# Generated by FakeRAM 2.0
VERSION 5.7 ;
BUSBITCHARS "[]" ;
PROPERTYDEFINITIONS
  MACRO width INTEGER ;
  MACRO depth INTEGER ;
  MACRO banks INTEGER ;
END PROPERTYDEFINITIONS
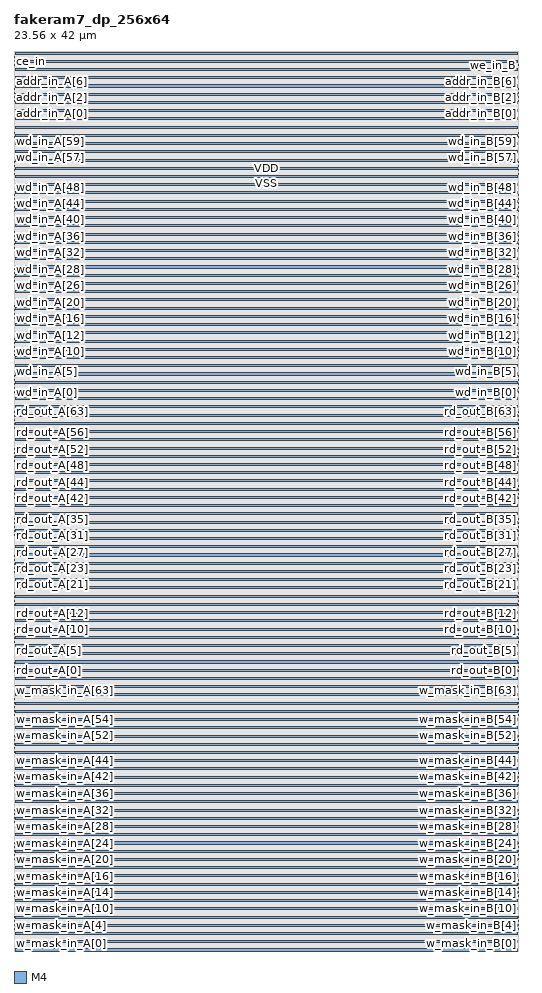
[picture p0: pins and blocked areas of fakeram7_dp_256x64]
MACRO fakeram7_dp_256x64
  PROPERTY width 64 ;
  PROPERTY depth 256 ;
  PROPERTY banks 2 ;
  FOREIGN fakeram7_dp_256x64 0 0 ;
  SYMMETRY X Y ;
  SIZE 23.560 BY 42.000 ;
  CLASS BLOCK ;
  PIN w_mask_in_A[0]
    DIRECTION INPUT ;
    USE SIGNAL ;
    SHAPE ABUTMENT ;
    PORT
      LAYER M4 ;
      RECT 0.000 0.048 0.024 0.072 ;
    END
  END w_mask_in_A[0]
  PIN w_mask_in_B[0]
    DIRECTION INPUT ;
    USE SIGNAL ;
    SHAPE ABUTMENT ;
    PORT
      LAYER M4 ;
      RECT 23.536 0.048 23.560 0.072 ;
    END
  END w_mask_in_B[0]
  PIN w_mask_in_A[1]
    DIRECTION INPUT ;
    USE SIGNAL ;
    SHAPE ABUTMENT ;
    PORT
      LAYER M4 ;
      RECT 0.000 0.240 0.024 0.264 ;
    END
  END w_mask_in_A[1]
  PIN w_mask_in_B[1]
    DIRECTION INPUT ;
    USE SIGNAL ;
    SHAPE ABUTMENT ;
    PORT
      LAYER M4 ;
      RECT 23.536 0.240 23.560 0.264 ;
    END
  END w_mask_in_B[1]
  PIN w_mask_in_A[2]
    DIRECTION INPUT ;
    USE SIGNAL ;
    SHAPE ABUTMENT ;
    PORT
      LAYER M4 ;
      RECT 0.000 0.432 0.024 0.456 ;
    END
  END w_mask_in_A[2]
  PIN w_mask_in_B[2]
    DIRECTION INPUT ;
    USE SIGNAL ;
    SHAPE ABUTMENT ;
    PORT
      LAYER M4 ;
      RECT 23.536 0.432 23.560 0.456 ;
    END
  END w_mask_in_B[2]
  PIN w_mask_in_A[3]
    DIRECTION INPUT ;
    USE SIGNAL ;
    SHAPE ABUTMENT ;
    PORT
      LAYER M4 ;
      RECT 0.000 0.624 0.024 0.648 ;
    END
  END w_mask_in_A[3]
  PIN w_mask_in_B[3]
    DIRECTION INPUT ;
    USE SIGNAL ;
    SHAPE ABUTMENT ;
    PORT
      LAYER M4 ;
      RECT 23.536 0.624 23.560 0.648 ;
    END
  END w_mask_in_B[3]
  PIN w_mask_in_A[4]
    DIRECTION INPUT ;
    USE SIGNAL ;
    SHAPE ABUTMENT ;
    PORT
      LAYER M4 ;
      RECT 0.000 0.816 0.024 0.840 ;
    END
  END w_mask_in_A[4]
  PIN w_mask_in_B[4]
    DIRECTION INPUT ;
    USE SIGNAL ;
    SHAPE ABUTMENT ;
    PORT
      LAYER M4 ;
      RECT 23.536 0.816 23.560 0.840 ;
    END
  END w_mask_in_B[4]
  PIN w_mask_in_A[5]
    DIRECTION INPUT ;
    USE SIGNAL ;
    SHAPE ABUTMENT ;
    PORT
      LAYER M4 ;
      RECT 0.000 1.008 0.024 1.032 ;
    END
  END w_mask_in_A[5]
  PIN w_mask_in_B[5]
    DIRECTION INPUT ;
    USE SIGNAL ;
    SHAPE ABUTMENT ;
    PORT
      LAYER M4 ;
      RECT 23.536 1.008 23.560 1.032 ;
    END
  END w_mask_in_B[5]
  PIN w_mask_in_A[6]
    DIRECTION INPUT ;
    USE SIGNAL ;
    SHAPE ABUTMENT ;
    PORT
      LAYER M4 ;
      RECT 0.000 1.200 0.024 1.224 ;
    END
  END w_mask_in_A[6]
  PIN w_mask_in_B[6]
    DIRECTION INPUT ;
    USE SIGNAL ;
    SHAPE ABUTMENT ;
    PORT
      LAYER M4 ;
      RECT 23.536 1.200 23.560 1.224 ;
    END
  END w_mask_in_B[6]
  PIN w_mask_in_A[7]
    DIRECTION INPUT ;
    USE SIGNAL ;
    SHAPE ABUTMENT ;
    PORT
      LAYER M4 ;
      RECT 0.000 1.392 0.024 1.416 ;
    END
  END w_mask_in_A[7]
  PIN w_mask_in_B[7]
    DIRECTION INPUT ;
    USE SIGNAL ;
    SHAPE ABUTMENT ;
    PORT
      LAYER M4 ;
      RECT 23.536 1.392 23.560 1.416 ;
    END
  END w_mask_in_B[7]
  PIN w_mask_in_A[8]
    DIRECTION INPUT ;
    USE SIGNAL ;
    SHAPE ABUTMENT ;
    PORT
      LAYER M4 ;
      RECT 0.000 1.584 0.024 1.608 ;
    END
  END w_mask_in_A[8]
  PIN w_mask_in_B[8]
    DIRECTION INPUT ;
    USE SIGNAL ;
    SHAPE ABUTMENT ;
    PORT
      LAYER M4 ;
      RECT 23.536 1.584 23.560 1.608 ;
    END
  END w_mask_in_B[8]
  PIN w_mask_in_A[9]
    DIRECTION INPUT ;
    USE SIGNAL ;
    SHAPE ABUTMENT ;
    PORT
      LAYER M4 ;
      RECT 0.000 1.776 0.024 1.800 ;
    END
  END w_mask_in_A[9]
  PIN w_mask_in_B[9]
    DIRECTION INPUT ;
    USE SIGNAL ;
    SHAPE ABUTMENT ;
    PORT
      LAYER M4 ;
      RECT 23.536 1.776 23.560 1.800 ;
    END
  END w_mask_in_B[9]
  PIN w_mask_in_A[10]
    DIRECTION INPUT ;
    USE SIGNAL ;
    SHAPE ABUTMENT ;
    PORT
      LAYER M4 ;
      RECT 0.000 1.968 0.024 1.992 ;
    END
  END w_mask_in_A[10]
  PIN w_mask_in_B[10]
    DIRECTION INPUT ;
    USE SIGNAL ;
    SHAPE ABUTMENT ;
    PORT
      LAYER M4 ;
      RECT 23.536 1.968 23.560 1.992 ;
    END
  END w_mask_in_B[10]
  PIN w_mask_in_A[11]
    DIRECTION INPUT ;
    USE SIGNAL ;
    SHAPE ABUTMENT ;
    PORT
      LAYER M4 ;
      RECT 0.000 2.160 0.024 2.184 ;
    END
  END w_mask_in_A[11]
  PIN w_mask_in_B[11]
    DIRECTION INPUT ;
    USE SIGNAL ;
    SHAPE ABUTMENT ;
    PORT
      LAYER M4 ;
      RECT 23.536 2.160 23.560 2.184 ;
    END
  END w_mask_in_B[11]
  PIN w_mask_in_A[12]
    DIRECTION INPUT ;
    USE SIGNAL ;
    SHAPE ABUTMENT ;
    PORT
      LAYER M4 ;
      RECT 0.000 2.352 0.024 2.376 ;
    END
  END w_mask_in_A[12]
  PIN w_mask_in_B[12]
    DIRECTION INPUT ;
    USE SIGNAL ;
    SHAPE ABUTMENT ;
    PORT
      LAYER M4 ;
      RECT 23.536 2.352 23.560 2.376 ;
    END
  END w_mask_in_B[12]
  PIN w_mask_in_A[13]
    DIRECTION INPUT ;
    USE SIGNAL ;
    SHAPE ABUTMENT ;
    PORT
      LAYER M4 ;
      RECT 0.000 2.544 0.024 2.568 ;
    END
  END w_mask_in_A[13]
  PIN w_mask_in_B[13]
    DIRECTION INPUT ;
    USE SIGNAL ;
    SHAPE ABUTMENT ;
    PORT
      LAYER M4 ;
      RECT 23.536 2.544 23.560 2.568 ;
    END
  END w_mask_in_B[13]
  PIN w_mask_in_A[14]
    DIRECTION INPUT ;
    USE SIGNAL ;
    SHAPE ABUTMENT ;
    PORT
      LAYER M4 ;
      RECT 0.000 2.736 0.024 2.760 ;
    END
  END w_mask_in_A[14]
  PIN w_mask_in_B[14]
    DIRECTION INPUT ;
    USE SIGNAL ;
    SHAPE ABUTMENT ;
    PORT
      LAYER M4 ;
      RECT 23.536 2.736 23.560 2.760 ;
    END
  END w_mask_in_B[14]
  PIN w_mask_in_A[15]
    DIRECTION INPUT ;
    USE SIGNAL ;
    SHAPE ABUTMENT ;
    PORT
      LAYER M4 ;
      RECT 0.000 2.928 0.024 2.952 ;
    END
  END w_mask_in_A[15]
  PIN w_mask_in_B[15]
    DIRECTION INPUT ;
    USE SIGNAL ;
    SHAPE ABUTMENT ;
    PORT
      LAYER M4 ;
      RECT 23.536 2.928 23.560 2.952 ;
    END
  END w_mask_in_B[15]
  PIN w_mask_in_A[16]
    DIRECTION INPUT ;
    USE SIGNAL ;
    SHAPE ABUTMENT ;
    PORT
      LAYER M4 ;
      RECT 0.000 3.120 0.024 3.144 ;
    END
  END w_mask_in_A[16]
  PIN w_mask_in_B[16]
    DIRECTION INPUT ;
    USE SIGNAL ;
    SHAPE ABUTMENT ;
    PORT
      LAYER M4 ;
      RECT 23.536 3.120 23.560 3.144 ;
    END
  END w_mask_in_B[16]
  PIN w_mask_in_A[17]
    DIRECTION INPUT ;
    USE SIGNAL ;
    SHAPE ABUTMENT ;
    PORT
      LAYER M4 ;
      RECT 0.000 3.312 0.024 3.336 ;
    END
  END w_mask_in_A[17]
  PIN w_mask_in_B[17]
    DIRECTION INPUT ;
    USE SIGNAL ;
    SHAPE ABUTMENT ;
    PORT
      LAYER M4 ;
      RECT 23.536 3.312 23.560 3.336 ;
    END
  END w_mask_in_B[17]
  PIN w_mask_in_A[18]
    DIRECTION INPUT ;
    USE SIGNAL ;
    SHAPE ABUTMENT ;
    PORT
      LAYER M4 ;
      RECT 0.000 3.504 0.024 3.528 ;
    END
  END w_mask_in_A[18]
  PIN w_mask_in_B[18]
    DIRECTION INPUT ;
    USE SIGNAL ;
    SHAPE ABUTMENT ;
    PORT
      LAYER M4 ;
      RECT 23.536 3.504 23.560 3.528 ;
    END
  END w_mask_in_B[18]
  PIN w_mask_in_A[19]
    DIRECTION INPUT ;
    USE SIGNAL ;
    SHAPE ABUTMENT ;
    PORT
      LAYER M4 ;
      RECT 0.000 3.696 0.024 3.720 ;
    END
  END w_mask_in_A[19]
  PIN w_mask_in_B[19]
    DIRECTION INPUT ;
    USE SIGNAL ;
    SHAPE ABUTMENT ;
    PORT
      LAYER M4 ;
      RECT 23.536 3.696 23.560 3.720 ;
    END
  END w_mask_in_B[19]
  PIN w_mask_in_A[20]
    DIRECTION INPUT ;
    USE SIGNAL ;
    SHAPE ABUTMENT ;
    PORT
      LAYER M4 ;
      RECT 0.000 3.888 0.024 3.912 ;
    END
  END w_mask_in_A[20]
  PIN w_mask_in_B[20]
    DIRECTION INPUT ;
    USE SIGNAL ;
    SHAPE ABUTMENT ;
    PORT
      LAYER M4 ;
      RECT 23.536 3.888 23.560 3.912 ;
    END
  END w_mask_in_B[20]
  PIN w_mask_in_A[21]
    DIRECTION INPUT ;
    USE SIGNAL ;
    SHAPE ABUTMENT ;
    PORT
      LAYER M4 ;
      RECT 0.000 4.080 0.024 4.104 ;
    END
  END w_mask_in_A[21]
  PIN w_mask_in_B[21]
    DIRECTION INPUT ;
    USE SIGNAL ;
    SHAPE ABUTMENT ;
    PORT
      LAYER M4 ;
      RECT 23.536 4.080 23.560 4.104 ;
    END
  END w_mask_in_B[21]
  PIN w_mask_in_A[22]
    DIRECTION INPUT ;
    USE SIGNAL ;
    SHAPE ABUTMENT ;
    PORT
      LAYER M4 ;
      RECT 0.000 4.272 0.024 4.296 ;
    END
  END w_mask_in_A[22]
  PIN w_mask_in_B[22]
    DIRECTION INPUT ;
    USE SIGNAL ;
    SHAPE ABUTMENT ;
    PORT
      LAYER M4 ;
      RECT 23.536 4.272 23.560 4.296 ;
    END
  END w_mask_in_B[22]
  PIN w_mask_in_A[23]
    DIRECTION INPUT ;
    USE SIGNAL ;
    SHAPE ABUTMENT ;
    PORT
      LAYER M4 ;
      RECT 0.000 4.464 0.024 4.488 ;
    END
  END w_mask_in_A[23]
  PIN w_mask_in_B[23]
    DIRECTION INPUT ;
    USE SIGNAL ;
    SHAPE ABUTMENT ;
    PORT
      LAYER M4 ;
      RECT 23.536 4.464 23.560 4.488 ;
    END
  END w_mask_in_B[23]
  PIN w_mask_in_A[24]
    DIRECTION INPUT ;
    USE SIGNAL ;
    SHAPE ABUTMENT ;
    PORT
      LAYER M4 ;
      RECT 0.000 4.656 0.024 4.680 ;
    END
  END w_mask_in_A[24]
  PIN w_mask_in_B[24]
    DIRECTION INPUT ;
    USE SIGNAL ;
    SHAPE ABUTMENT ;
    PORT
      LAYER M4 ;
      RECT 23.536 4.656 23.560 4.680 ;
    END
  END w_mask_in_B[24]
  PIN w_mask_in_A[25]
    DIRECTION INPUT ;
    USE SIGNAL ;
    SHAPE ABUTMENT ;
    PORT
      LAYER M4 ;
      RECT 0.000 4.848 0.024 4.872 ;
    END
  END w_mask_in_A[25]
  PIN w_mask_in_B[25]
    DIRECTION INPUT ;
    USE SIGNAL ;
    SHAPE ABUTMENT ;
    PORT
      LAYER M4 ;
      RECT 23.536 4.848 23.560 4.872 ;
    END
  END w_mask_in_B[25]
  PIN w_mask_in_A[26]
    DIRECTION INPUT ;
    USE SIGNAL ;
    SHAPE ABUTMENT ;
    PORT
      LAYER M4 ;
      RECT 0.000 5.040 0.024 5.064 ;
    END
  END w_mask_in_A[26]
  PIN w_mask_in_B[26]
    DIRECTION INPUT ;
    USE SIGNAL ;
    SHAPE ABUTMENT ;
    PORT
      LAYER M4 ;
      RECT 23.536 5.040 23.560 5.064 ;
    END
  END w_mask_in_B[26]
  PIN w_mask_in_A[27]
    DIRECTION INPUT ;
    USE SIGNAL ;
    SHAPE ABUTMENT ;
    PORT
      LAYER M4 ;
      RECT 0.000 5.232 0.024 5.256 ;
    END
  END w_mask_in_A[27]
  PIN w_mask_in_B[27]
    DIRECTION INPUT ;
    USE SIGNAL ;
    SHAPE ABUTMENT ;
    PORT
      LAYER M4 ;
      RECT 23.536 5.232 23.560 5.256 ;
    END
  END w_mask_in_B[27]
  PIN w_mask_in_A[28]
    DIRECTION INPUT ;
    USE SIGNAL ;
    SHAPE ABUTMENT ;
    PORT
      LAYER M4 ;
      RECT 0.000 5.424 0.024 5.448 ;
    END
  END w_mask_in_A[28]
  PIN w_mask_in_B[28]
    DIRECTION INPUT ;
    USE SIGNAL ;
    SHAPE ABUTMENT ;
    PORT
      LAYER M4 ;
      RECT 23.536 5.424 23.560 5.448 ;
    END
  END w_mask_in_B[28]
  PIN w_mask_in_A[29]
    DIRECTION INPUT ;
    USE SIGNAL ;
    SHAPE ABUTMENT ;
    PORT
      LAYER M4 ;
      RECT 0.000 5.616 0.024 5.640 ;
    END
  END w_mask_in_A[29]
  PIN w_mask_in_B[29]
    DIRECTION INPUT ;
    USE SIGNAL ;
    SHAPE ABUTMENT ;
    PORT
      LAYER M4 ;
      RECT 23.536 5.616 23.560 5.640 ;
    END
  END w_mask_in_B[29]
  PIN w_mask_in_A[30]
    DIRECTION INPUT ;
    USE SIGNAL ;
    SHAPE ABUTMENT ;
    PORT
      LAYER M4 ;
      RECT 0.000 5.808 0.024 5.832 ;
    END
  END w_mask_in_A[30]
  PIN w_mask_in_B[30]
    DIRECTION INPUT ;
    USE SIGNAL ;
    SHAPE ABUTMENT ;
    PORT
      LAYER M4 ;
      RECT 23.536 5.808 23.560 5.832 ;
    END
  END w_mask_in_B[30]
  PIN w_mask_in_A[31]
    DIRECTION INPUT ;
    USE SIGNAL ;
    SHAPE ABUTMENT ;
    PORT
      LAYER M4 ;
      RECT 0.000 6.000 0.024 6.024 ;
    END
  END w_mask_in_A[31]
  PIN w_mask_in_B[31]
    DIRECTION INPUT ;
    USE SIGNAL ;
    SHAPE ABUTMENT ;
    PORT
      LAYER M4 ;
      RECT 23.536 6.000 23.560 6.024 ;
    END
  END w_mask_in_B[31]
  PIN w_mask_in_A[32]
    DIRECTION INPUT ;
    USE SIGNAL ;
    SHAPE ABUTMENT ;
    PORT
      LAYER M4 ;
      RECT 0.000 6.192 0.024 6.216 ;
    END
  END w_mask_in_A[32]
  PIN w_mask_in_B[32]
    DIRECTION INPUT ;
    USE SIGNAL ;
    SHAPE ABUTMENT ;
    PORT
      LAYER M4 ;
      RECT 23.536 6.192 23.560 6.216 ;
    END
  END w_mask_in_B[32]
  PIN w_mask_in_A[33]
    DIRECTION INPUT ;
    USE SIGNAL ;
    SHAPE ABUTMENT ;
    PORT
      LAYER M4 ;
      RECT 0.000 6.384 0.024 6.408 ;
    END
  END w_mask_in_A[33]
  PIN w_mask_in_B[33]
    DIRECTION INPUT ;
    USE SIGNAL ;
    SHAPE ABUTMENT ;
    PORT
      LAYER M4 ;
      RECT 23.536 6.384 23.560 6.408 ;
    END
  END w_mask_in_B[33]
  PIN w_mask_in_A[34]
    DIRECTION INPUT ;
    USE SIGNAL ;
    SHAPE ABUTMENT ;
    PORT
      LAYER M4 ;
      RECT 0.000 6.576 0.024 6.600 ;
    END
  END w_mask_in_A[34]
  PIN w_mask_in_B[34]
    DIRECTION INPUT ;
    USE SIGNAL ;
    SHAPE ABUTMENT ;
    PORT
      LAYER M4 ;
      RECT 23.536 6.576 23.560 6.600 ;
    END
  END w_mask_in_B[34]
  PIN w_mask_in_A[35]
    DIRECTION INPUT ;
    USE SIGNAL ;
    SHAPE ABUTMENT ;
    PORT
      LAYER M4 ;
      RECT 0.000 6.768 0.024 6.792 ;
    END
  END w_mask_in_A[35]
  PIN w_mask_in_B[35]
    DIRECTION INPUT ;
    USE SIGNAL ;
    SHAPE ABUTMENT ;
    PORT
      LAYER M4 ;
      RECT 23.536 6.768 23.560 6.792 ;
    END
  END w_mask_in_B[35]
  PIN w_mask_in_A[36]
    DIRECTION INPUT ;
    USE SIGNAL ;
    SHAPE ABUTMENT ;
    PORT
      LAYER M4 ;
      RECT 0.000 6.960 0.024 6.984 ;
    END
  END w_mask_in_A[36]
  PIN w_mask_in_B[36]
    DIRECTION INPUT ;
    USE SIGNAL ;
    SHAPE ABUTMENT ;
    PORT
      LAYER M4 ;
      RECT 23.536 6.960 23.560 6.984 ;
    END
  END w_mask_in_B[36]
  PIN w_mask_in_A[37]
    DIRECTION INPUT ;
    USE SIGNAL ;
    SHAPE ABUTMENT ;
    PORT
      LAYER M4 ;
      RECT 0.000 7.152 0.024 7.176 ;
    END
  END w_mask_in_A[37]
  PIN w_mask_in_B[37]
    DIRECTION INPUT ;
    USE SIGNAL ;
    SHAPE ABUTMENT ;
    PORT
      LAYER M4 ;
      RECT 23.536 7.152 23.560 7.176 ;
    END
  END w_mask_in_B[37]
  PIN w_mask_in_A[38]
    DIRECTION INPUT ;
    USE SIGNAL ;
    SHAPE ABUTMENT ;
    PORT
      LAYER M4 ;
      RECT 0.000 7.344 0.024 7.368 ;
    END
  END w_mask_in_A[38]
  PIN w_mask_in_B[38]
    DIRECTION INPUT ;
    USE SIGNAL ;
    SHAPE ABUTMENT ;
    PORT
      LAYER M4 ;
      RECT 23.536 7.344 23.560 7.368 ;
    END
  END w_mask_in_B[38]
  PIN w_mask_in_A[39]
    DIRECTION INPUT ;
    USE SIGNAL ;
    SHAPE ABUTMENT ;
    PORT
      LAYER M4 ;
      RECT 0.000 7.536 0.024 7.560 ;
    END
  END w_mask_in_A[39]
  PIN w_mask_in_B[39]
    DIRECTION INPUT ;
    USE SIGNAL ;
    SHAPE ABUTMENT ;
    PORT
      LAYER M4 ;
      RECT 23.536 7.536 23.560 7.560 ;
    END
  END w_mask_in_B[39]
  PIN w_mask_in_A[40]
    DIRECTION INPUT ;
    USE SIGNAL ;
    SHAPE ABUTMENT ;
    PORT
      LAYER M4 ;
      RECT 0.000 7.728 0.024 7.752 ;
    END
  END w_mask_in_A[40]
  PIN w_mask_in_B[40]
    DIRECTION INPUT ;
    USE SIGNAL ;
    SHAPE ABUTMENT ;
    PORT
      LAYER M4 ;
      RECT 23.536 7.728 23.560 7.752 ;
    END
  END w_mask_in_B[40]
  PIN w_mask_in_A[41]
    DIRECTION INPUT ;
    USE SIGNAL ;
    SHAPE ABUTMENT ;
    PORT
      LAYER M4 ;
      RECT 0.000 7.920 0.024 7.944 ;
    END
  END w_mask_in_A[41]
  PIN w_mask_in_B[41]
    DIRECTION INPUT ;
    USE SIGNAL ;
    SHAPE ABUTMENT ;
    PORT
      LAYER M4 ;
      RECT 23.536 7.920 23.560 7.944 ;
    END
  END w_mask_in_B[41]
  PIN w_mask_in_A[42]
    DIRECTION INPUT ;
    USE SIGNAL ;
    SHAPE ABUTMENT ;
    PORT
      LAYER M4 ;
      RECT 0.000 8.112 0.024 8.136 ;
    END
  END w_mask_in_A[42]
  PIN w_mask_in_B[42]
    DIRECTION INPUT ;
    USE SIGNAL ;
    SHAPE ABUTMENT ;
    PORT
      LAYER M4 ;
      RECT 23.536 8.112 23.560 8.136 ;
    END
  END w_mask_in_B[42]
  PIN w_mask_in_A[43]
    DIRECTION INPUT ;
    USE SIGNAL ;
    SHAPE ABUTMENT ;
    PORT
      LAYER M4 ;
      RECT 0.000 8.304 0.024 8.328 ;
    END
  END w_mask_in_A[43]
  PIN w_mask_in_B[43]
    DIRECTION INPUT ;
    USE SIGNAL ;
    SHAPE ABUTMENT ;
    PORT
      LAYER M4 ;
      RECT 23.536 8.304 23.560 8.328 ;
    END
  END w_mask_in_B[43]
  PIN w_mask_in_A[44]
    DIRECTION INPUT ;
    USE SIGNAL ;
    SHAPE ABUTMENT ;
    PORT
      LAYER M4 ;
      RECT 0.000 8.496 0.024 8.520 ;
    END
  END w_mask_in_A[44]
  PIN w_mask_in_B[44]
    DIRECTION INPUT ;
    USE SIGNAL ;
    SHAPE ABUTMENT ;
    PORT
      LAYER M4 ;
      RECT 23.536 8.496 23.560 8.520 ;
    END
  END w_mask_in_B[44]
  PIN w_mask_in_A[45]
    DIRECTION INPUT ;
    USE SIGNAL ;
    SHAPE ABUTMENT ;
    PORT
      LAYER M4 ;
      RECT 0.000 8.688 0.024 8.712 ;
    END
  END w_mask_in_A[45]
  PIN w_mask_in_B[45]
    DIRECTION INPUT ;
    USE SIGNAL ;
    SHAPE ABUTMENT ;
    PORT
      LAYER M4 ;
      RECT 23.536 8.688 23.560 8.712 ;
    END
  END w_mask_in_B[45]
  PIN w_mask_in_A[46]
    DIRECTION INPUT ;
    USE SIGNAL ;
    SHAPE ABUTMENT ;
    PORT
      LAYER M4 ;
      RECT 0.000 8.880 0.024 8.904 ;
    END
  END w_mask_in_A[46]
  PIN w_mask_in_B[46]
    DIRECTION INPUT ;
    USE SIGNAL ;
    SHAPE ABUTMENT ;
    PORT
      LAYER M4 ;
      RECT 23.536 8.880 23.560 8.904 ;
    END
  END w_mask_in_B[46]
  PIN w_mask_in_A[47]
    DIRECTION INPUT ;
    USE SIGNAL ;
    SHAPE ABUTMENT ;
    PORT
      LAYER M4 ;
      RECT 0.000 9.072 0.024 9.096 ;
    END
  END w_mask_in_A[47]
  PIN w_mask_in_B[47]
    DIRECTION INPUT ;
    USE SIGNAL ;
    SHAPE ABUTMENT ;
    PORT
      LAYER M4 ;
      RECT 23.536 9.072 23.560 9.096 ;
    END
  END w_mask_in_B[47]
  PIN w_mask_in_A[48]
    DIRECTION INPUT ;
    USE SIGNAL ;
    SHAPE ABUTMENT ;
    PORT
      LAYER M4 ;
      RECT 0.000 9.264 0.024 9.288 ;
    END
  END w_mask_in_A[48]
  PIN w_mask_in_B[48]
    DIRECTION INPUT ;
    USE SIGNAL ;
    SHAPE ABUTMENT ;
    PORT
      LAYER M4 ;
      RECT 23.536 9.264 23.560 9.288 ;
    END
  END w_mask_in_B[48]
  PIN w_mask_in_A[49]
    DIRECTION INPUT ;
    USE SIGNAL ;
    SHAPE ABUTMENT ;
    PORT
      LAYER M4 ;
      RECT 0.000 9.456 0.024 9.480 ;
    END
  END w_mask_in_A[49]
  PIN w_mask_in_B[49]
    DIRECTION INPUT ;
    USE SIGNAL ;
    SHAPE ABUTMENT ;
    PORT
      LAYER M4 ;
      RECT 23.536 9.456 23.560 9.480 ;
    END
  END w_mask_in_B[49]
  PIN w_mask_in_A[50]
    DIRECTION INPUT ;
    USE SIGNAL ;
    SHAPE ABUTMENT ;
    PORT
      LAYER M4 ;
      RECT 0.000 9.648 0.024 9.672 ;
    END
  END w_mask_in_A[50]
  PIN w_mask_in_B[50]
    DIRECTION INPUT ;
    USE SIGNAL ;
    SHAPE ABUTMENT ;
    PORT
      LAYER M4 ;
      RECT 23.536 9.648 23.560 9.672 ;
    END
  END w_mask_in_B[50]
  PIN w_mask_in_A[51]
    DIRECTION INPUT ;
    USE SIGNAL ;
    SHAPE ABUTMENT ;
    PORT
      LAYER M4 ;
      RECT 0.000 9.840 0.024 9.864 ;
    END
  END w_mask_in_A[51]
  PIN w_mask_in_B[51]
    DIRECTION INPUT ;
    USE SIGNAL ;
    SHAPE ABUTMENT ;
    PORT
      LAYER M4 ;
      RECT 23.536 9.840 23.560 9.864 ;
    END
  END w_mask_in_B[51]
  PIN w_mask_in_A[52]
    DIRECTION INPUT ;
    USE SIGNAL ;
    SHAPE ABUTMENT ;
    PORT
      LAYER M4 ;
      RECT 0.000 10.032 0.024 10.056 ;
    END
  END w_mask_in_A[52]
  PIN w_mask_in_B[52]
    DIRECTION INPUT ;
    USE SIGNAL ;
    SHAPE ABUTMENT ;
    PORT
      LAYER M4 ;
      RECT 23.536 10.032 23.560 10.056 ;
    END
  END w_mask_in_B[52]
  PIN w_mask_in_A[53]
    DIRECTION INPUT ;
    USE SIGNAL ;
    SHAPE ABUTMENT ;
    PORT
      LAYER M4 ;
      RECT 0.000 10.224 0.024 10.248 ;
    END
  END w_mask_in_A[53]
  PIN w_mask_in_B[53]
    DIRECTION INPUT ;
    USE SIGNAL ;
    SHAPE ABUTMENT ;
    PORT
      LAYER M4 ;
      RECT 23.536 10.224 23.560 10.248 ;
    END
  END w_mask_in_B[53]
  PIN w_mask_in_A[54]
    DIRECTION INPUT ;
    USE SIGNAL ;
    SHAPE ABUTMENT ;
    PORT
      LAYER M4 ;
      RECT 0.000 10.416 0.024 10.440 ;
    END
  END w_mask_in_A[54]
  PIN w_mask_in_B[54]
    DIRECTION INPUT ;
    USE SIGNAL ;
    SHAPE ABUTMENT ;
    PORT
      LAYER M4 ;
      RECT 23.536 10.416 23.560 10.440 ;
    END
  END w_mask_in_B[54]
  PIN w_mask_in_A[55]
    DIRECTION INPUT ;
    USE SIGNAL ;
    SHAPE ABUTMENT ;
    PORT
      LAYER M4 ;
      RECT 0.000 10.608 0.024 10.632 ;
    END
  END w_mask_in_A[55]
  PIN w_mask_in_B[55]
    DIRECTION INPUT ;
    USE SIGNAL ;
    SHAPE ABUTMENT ;
    PORT
      LAYER M4 ;
      RECT 23.536 10.608 23.560 10.632 ;
    END
  END w_mask_in_B[55]
  PIN w_mask_in_A[56]
    DIRECTION INPUT ;
    USE SIGNAL ;
    SHAPE ABUTMENT ;
    PORT
      LAYER M4 ;
      RECT 0.000 10.800 0.024 10.824 ;
    END
  END w_mask_in_A[56]
  PIN w_mask_in_B[56]
    DIRECTION INPUT ;
    USE SIGNAL ;
    SHAPE ABUTMENT ;
    PORT
      LAYER M4 ;
      RECT 23.536 10.800 23.560 10.824 ;
    END
  END w_mask_in_B[56]
  PIN w_mask_in_A[57]
    DIRECTION INPUT ;
    USE SIGNAL ;
    SHAPE ABUTMENT ;
    PORT
      LAYER M4 ;
      RECT 0.000 10.992 0.024 11.016 ;
    END
  END w_mask_in_A[57]
  PIN w_mask_in_B[57]
    DIRECTION INPUT ;
    USE SIGNAL ;
    SHAPE ABUTMENT ;
    PORT
      LAYER M4 ;
      RECT 23.536 10.992 23.560 11.016 ;
    END
  END w_mask_in_B[57]
  PIN w_mask_in_A[58]
    DIRECTION INPUT ;
    USE SIGNAL ;
    SHAPE ABUTMENT ;
    PORT
      LAYER M4 ;
      RECT 0.000 11.184 0.024 11.208 ;
    END
  END w_mask_in_A[58]
  PIN w_mask_in_B[58]
    DIRECTION INPUT ;
    USE SIGNAL ;
    SHAPE ABUTMENT ;
    PORT
      LAYER M4 ;
      RECT 23.536 11.184 23.560 11.208 ;
    END
  END w_mask_in_B[58]
  PIN w_mask_in_A[59]
    DIRECTION INPUT ;
    USE SIGNAL ;
    SHAPE ABUTMENT ;
    PORT
      LAYER M4 ;
      RECT 0.000 11.376 0.024 11.400 ;
    END
  END w_mask_in_A[59]
  PIN w_mask_in_B[59]
    DIRECTION INPUT ;
    USE SIGNAL ;
    SHAPE ABUTMENT ;
    PORT
      LAYER M4 ;
      RECT 23.536 11.376 23.560 11.400 ;
    END
  END w_mask_in_B[59]
  PIN w_mask_in_A[60]
    DIRECTION INPUT ;
    USE SIGNAL ;
    SHAPE ABUTMENT ;
    PORT
      LAYER M4 ;
      RECT 0.000 11.568 0.024 11.592 ;
    END
  END w_mask_in_A[60]
  PIN w_mask_in_B[60]
    DIRECTION INPUT ;
    USE SIGNAL ;
    SHAPE ABUTMENT ;
    PORT
      LAYER M4 ;
      RECT 23.536 11.568 23.560 11.592 ;
    END
  END w_mask_in_B[60]
  PIN w_mask_in_A[61]
    DIRECTION INPUT ;
    USE SIGNAL ;
    SHAPE ABUTMENT ;
    PORT
      LAYER M4 ;
      RECT 0.000 11.760 0.024 11.784 ;
    END
  END w_mask_in_A[61]
  PIN w_mask_in_B[61]
    DIRECTION INPUT ;
    USE SIGNAL ;
    SHAPE ABUTMENT ;
    PORT
      LAYER M4 ;
      RECT 23.536 11.760 23.560 11.784 ;
    END
  END w_mask_in_B[61]
  PIN w_mask_in_A[62]
    DIRECTION INPUT ;
    USE SIGNAL ;
    SHAPE ABUTMENT ;
    PORT
      LAYER M4 ;
      RECT 0.000 11.952 0.024 11.976 ;
    END
  END w_mask_in_A[62]
  PIN w_mask_in_B[62]
    DIRECTION INPUT ;
    USE SIGNAL ;
    SHAPE ABUTMENT ;
    PORT
      LAYER M4 ;
      RECT 23.536 11.952 23.560 11.976 ;
    END
  END w_mask_in_B[62]
  PIN w_mask_in_A[63]
    DIRECTION INPUT ;
    USE SIGNAL ;
    SHAPE ABUTMENT ;
    PORT
      LAYER M4 ;
      RECT 0.000 12.144 0.024 12.168 ;
    END
  END w_mask_in_A[63]
  PIN w_mask_in_B[63]
    DIRECTION INPUT ;
    USE SIGNAL ;
    SHAPE ABUTMENT ;
    PORT
      LAYER M4 ;
      RECT 23.536 12.144 23.560 12.168 ;
    END
  END w_mask_in_B[63]
  PIN rd_out_A[0]
    DIRECTION OUTPUT ;
    USE SIGNAL ;
    SHAPE ABUTMENT ;
    PORT
      LAYER M4 ;
      RECT 0.000 13.056 0.024 13.080 ;
    END
  END rd_out_A[0]
  PIN rd_out_B[0]
    DIRECTION OUTPUT ;
    USE SIGNAL ;
    SHAPE ABUTMENT ;
    PORT
      LAYER M4 ;
      RECT 23.536 13.056 23.560 13.080 ;
    END
  END rd_out_B[0]
  PIN rd_out_A[1]
    DIRECTION OUTPUT ;
    USE SIGNAL ;
    SHAPE ABUTMENT ;
    PORT
      LAYER M4 ;
      RECT 0.000 13.248 0.024 13.272 ;
    END
  END rd_out_A[1]
  PIN rd_out_B[1]
    DIRECTION OUTPUT ;
    USE SIGNAL ;
    SHAPE ABUTMENT ;
    PORT
      LAYER M4 ;
      RECT 23.536 13.248 23.560 13.272 ;
    END
  END rd_out_B[1]
  PIN rd_out_A[2]
    DIRECTION OUTPUT ;
    USE SIGNAL ;
    SHAPE ABUTMENT ;
    PORT
      LAYER M4 ;
      RECT 0.000 13.440 0.024 13.464 ;
    END
  END rd_out_A[2]
  PIN rd_out_B[2]
    DIRECTION OUTPUT ;
    USE SIGNAL ;
    SHAPE ABUTMENT ;
    PORT
      LAYER M4 ;
      RECT 23.536 13.440 23.560 13.464 ;
    END
  END rd_out_B[2]
  PIN rd_out_A[3]
    DIRECTION OUTPUT ;
    USE SIGNAL ;
    SHAPE ABUTMENT ;
    PORT
      LAYER M4 ;
      RECT 0.000 13.632 0.024 13.656 ;
    END
  END rd_out_A[3]
  PIN rd_out_B[3]
    DIRECTION OUTPUT ;
    USE SIGNAL ;
    SHAPE ABUTMENT ;
    PORT
      LAYER M4 ;
      RECT 23.536 13.632 23.560 13.656 ;
    END
  END rd_out_B[3]
  PIN rd_out_A[4]
    DIRECTION OUTPUT ;
    USE SIGNAL ;
    SHAPE ABUTMENT ;
    PORT
      LAYER M4 ;
      RECT 0.000 13.824 0.024 13.848 ;
    END
  END rd_out_A[4]
  PIN rd_out_B[4]
    DIRECTION OUTPUT ;
    USE SIGNAL ;
    SHAPE ABUTMENT ;
    PORT
      LAYER M4 ;
      RECT 23.536 13.824 23.560 13.848 ;
    END
  END rd_out_B[4]
  PIN rd_out_A[5]
    DIRECTION OUTPUT ;
    USE SIGNAL ;
    SHAPE ABUTMENT ;
    PORT
      LAYER M4 ;
      RECT 0.000 14.016 0.024 14.040 ;
    END
  END rd_out_A[5]
  PIN rd_out_B[5]
    DIRECTION OUTPUT ;
    USE SIGNAL ;
    SHAPE ABUTMENT ;
    PORT
      LAYER M4 ;
      RECT 23.536 14.016 23.560 14.040 ;
    END
  END rd_out_B[5]
  PIN rd_out_A[6]
    DIRECTION OUTPUT ;
    USE SIGNAL ;
    SHAPE ABUTMENT ;
    PORT
      LAYER M4 ;
      RECT 0.000 14.208 0.024 14.232 ;
    END
  END rd_out_A[6]
  PIN rd_out_B[6]
    DIRECTION OUTPUT ;
    USE SIGNAL ;
    SHAPE ABUTMENT ;
    PORT
      LAYER M4 ;
      RECT 23.536 14.208 23.560 14.232 ;
    END
  END rd_out_B[6]
  PIN rd_out_A[7]
    DIRECTION OUTPUT ;
    USE SIGNAL ;
    SHAPE ABUTMENT ;
    PORT
      LAYER M4 ;
      RECT 0.000 14.400 0.024 14.424 ;
    END
  END rd_out_A[7]
  PIN rd_out_B[7]
    DIRECTION OUTPUT ;
    USE SIGNAL ;
    SHAPE ABUTMENT ;
    PORT
      LAYER M4 ;
      RECT 23.536 14.400 23.560 14.424 ;
    END
  END rd_out_B[7]
  PIN rd_out_A[8]
    DIRECTION OUTPUT ;
    USE SIGNAL ;
    SHAPE ABUTMENT ;
    PORT
      LAYER M4 ;
      RECT 0.000 14.592 0.024 14.616 ;
    END
  END rd_out_A[8]
  PIN rd_out_B[8]
    DIRECTION OUTPUT ;
    USE SIGNAL ;
    SHAPE ABUTMENT ;
    PORT
      LAYER M4 ;
      RECT 23.536 14.592 23.560 14.616 ;
    END
  END rd_out_B[8]
  PIN rd_out_A[9]
    DIRECTION OUTPUT ;
    USE SIGNAL ;
    SHAPE ABUTMENT ;
    PORT
      LAYER M4 ;
      RECT 0.000 14.784 0.024 14.808 ;
    END
  END rd_out_A[9]
  PIN rd_out_B[9]
    DIRECTION OUTPUT ;
    USE SIGNAL ;
    SHAPE ABUTMENT ;
    PORT
      LAYER M4 ;
      RECT 23.536 14.784 23.560 14.808 ;
    END
  END rd_out_B[9]
  PIN rd_out_A[10]
    DIRECTION OUTPUT ;
    USE SIGNAL ;
    SHAPE ABUTMENT ;
    PORT
      LAYER M4 ;
      RECT 0.000 14.976 0.024 15.000 ;
    END
  END rd_out_A[10]
  PIN rd_out_B[10]
    DIRECTION OUTPUT ;
    USE SIGNAL ;
    SHAPE ABUTMENT ;
    PORT
      LAYER M4 ;
      RECT 23.536 14.976 23.560 15.000 ;
    END
  END rd_out_B[10]
  PIN rd_out_A[11]
    DIRECTION OUTPUT ;
    USE SIGNAL ;
    SHAPE ABUTMENT ;
    PORT
      LAYER M4 ;
      RECT 0.000 15.168 0.024 15.192 ;
    END
  END rd_out_A[11]
  PIN rd_out_B[11]
    DIRECTION OUTPUT ;
    USE SIGNAL ;
    SHAPE ABUTMENT ;
    PORT
      LAYER M4 ;
      RECT 23.536 15.168 23.560 15.192 ;
    END
  END rd_out_B[11]
  PIN rd_out_A[12]
    DIRECTION OUTPUT ;
    USE SIGNAL ;
    SHAPE ABUTMENT ;
    PORT
      LAYER M4 ;
      RECT 0.000 15.360 0.024 15.384 ;
    END
  END rd_out_A[12]
  PIN rd_out_B[12]
    DIRECTION OUTPUT ;
    USE SIGNAL ;
    SHAPE ABUTMENT ;
    PORT
      LAYER M4 ;
      RECT 23.536 15.360 23.560 15.384 ;
    END
  END rd_out_B[12]
  PIN rd_out_A[13]
    DIRECTION OUTPUT ;
    USE SIGNAL ;
    SHAPE ABUTMENT ;
    PORT
      LAYER M4 ;
      RECT 0.000 15.552 0.024 15.576 ;
    END
  END rd_out_A[13]
  PIN rd_out_B[13]
    DIRECTION OUTPUT ;
    USE SIGNAL ;
    SHAPE ABUTMENT ;
    PORT
      LAYER M4 ;
      RECT 23.536 15.552 23.560 15.576 ;
    END
  END rd_out_B[13]
  PIN rd_out_A[14]
    DIRECTION OUTPUT ;
    USE SIGNAL ;
    SHAPE ABUTMENT ;
    PORT
      LAYER M4 ;
      RECT 0.000 15.744 0.024 15.768 ;
    END
  END rd_out_A[14]
  PIN rd_out_B[14]
    DIRECTION OUTPUT ;
    USE SIGNAL ;
    SHAPE ABUTMENT ;
    PORT
      LAYER M4 ;
      RECT 23.536 15.744 23.560 15.768 ;
    END
  END rd_out_B[14]
  PIN rd_out_A[15]
    DIRECTION OUTPUT ;
    USE SIGNAL ;
    SHAPE ABUTMENT ;
    PORT
      LAYER M4 ;
      RECT 0.000 15.936 0.024 15.960 ;
    END
  END rd_out_A[15]
  PIN rd_out_B[15]
    DIRECTION OUTPUT ;
    USE SIGNAL ;
    SHAPE ABUTMENT ;
    PORT
      LAYER M4 ;
      RECT 23.536 15.936 23.560 15.960 ;
    END
  END rd_out_B[15]
  PIN rd_out_A[16]
    DIRECTION OUTPUT ;
    USE SIGNAL ;
    SHAPE ABUTMENT ;
    PORT
      LAYER M4 ;
      RECT 0.000 16.128 0.024 16.152 ;
    END
  END rd_out_A[16]
  PIN rd_out_B[16]
    DIRECTION OUTPUT ;
    USE SIGNAL ;
    SHAPE ABUTMENT ;
    PORT
      LAYER M4 ;
      RECT 23.536 16.128 23.560 16.152 ;
    END
  END rd_out_B[16]
  PIN rd_out_A[17]
    DIRECTION OUTPUT ;
    USE SIGNAL ;
    SHAPE ABUTMENT ;
    PORT
      LAYER M4 ;
      RECT 0.000 16.320 0.024 16.344 ;
    END
  END rd_out_A[17]
  PIN rd_out_B[17]
    DIRECTION OUTPUT ;
    USE SIGNAL ;
    SHAPE ABUTMENT ;
    PORT
      LAYER M4 ;
      RECT 23.536 16.320 23.560 16.344 ;
    END
  END rd_out_B[17]
  PIN rd_out_A[18]
    DIRECTION OUTPUT ;
    USE SIGNAL ;
    SHAPE ABUTMENT ;
    PORT
      LAYER M4 ;
      RECT 0.000 16.512 0.024 16.536 ;
    END
  END rd_out_A[18]
  PIN rd_out_B[18]
    DIRECTION OUTPUT ;
    USE SIGNAL ;
    SHAPE ABUTMENT ;
    PORT
      LAYER M4 ;
      RECT 23.536 16.512 23.560 16.536 ;
    END
  END rd_out_B[18]
  PIN rd_out_A[19]
    DIRECTION OUTPUT ;
    USE SIGNAL ;
    SHAPE ABUTMENT ;
    PORT
      LAYER M4 ;
      RECT 0.000 16.704 0.024 16.728 ;
    END
  END rd_out_A[19]
  PIN rd_out_B[19]
    DIRECTION OUTPUT ;
    USE SIGNAL ;
    SHAPE ABUTMENT ;
    PORT
      LAYER M4 ;
      RECT 23.536 16.704 23.560 16.728 ;
    END
  END rd_out_B[19]
  PIN rd_out_A[20]
    DIRECTION OUTPUT ;
    USE SIGNAL ;
    SHAPE ABUTMENT ;
    PORT
      LAYER M4 ;
      RECT 0.000 16.896 0.024 16.920 ;
    END
  END rd_out_A[20]
  PIN rd_out_B[20]
    DIRECTION OUTPUT ;
    USE SIGNAL ;
    SHAPE ABUTMENT ;
    PORT
      LAYER M4 ;
      RECT 23.536 16.896 23.560 16.920 ;
    END
  END rd_out_B[20]
  PIN rd_out_A[21]
    DIRECTION OUTPUT ;
    USE SIGNAL ;
    SHAPE ABUTMENT ;
    PORT
      LAYER M4 ;
      RECT 0.000 17.088 0.024 17.112 ;
    END
  END rd_out_A[21]
  PIN rd_out_B[21]
    DIRECTION OUTPUT ;
    USE SIGNAL ;
    SHAPE ABUTMENT ;
    PORT
      LAYER M4 ;
      RECT 23.536 17.088 23.560 17.112 ;
    END
  END rd_out_B[21]
  PIN rd_out_A[22]
    DIRECTION OUTPUT ;
    USE SIGNAL ;
    SHAPE ABUTMENT ;
    PORT
      LAYER M4 ;
      RECT 0.000 17.280 0.024 17.304 ;
    END
  END rd_out_A[22]
  PIN rd_out_B[22]
    DIRECTION OUTPUT ;
    USE SIGNAL ;
    SHAPE ABUTMENT ;
    PORT
      LAYER M4 ;
      RECT 23.536 17.280 23.560 17.304 ;
    END
  END rd_out_B[22]
  PIN rd_out_A[23]
    DIRECTION OUTPUT ;
    USE SIGNAL ;
    SHAPE ABUTMENT ;
    PORT
      LAYER M4 ;
      RECT 0.000 17.472 0.024 17.496 ;
    END
  END rd_out_A[23]
  PIN rd_out_B[23]
    DIRECTION OUTPUT ;
    USE SIGNAL ;
    SHAPE ABUTMENT ;
    PORT
      LAYER M4 ;
      RECT 23.536 17.472 23.560 17.496 ;
    END
  END rd_out_B[23]
  PIN rd_out_A[24]
    DIRECTION OUTPUT ;
    USE SIGNAL ;
    SHAPE ABUTMENT ;
    PORT
      LAYER M4 ;
      RECT 0.000 17.664 0.024 17.688 ;
    END
  END rd_out_A[24]
  PIN rd_out_B[24]
    DIRECTION OUTPUT ;
    USE SIGNAL ;
    SHAPE ABUTMENT ;
    PORT
      LAYER M4 ;
      RECT 23.536 17.664 23.560 17.688 ;
    END
  END rd_out_B[24]
  PIN rd_out_A[25]
    DIRECTION OUTPUT ;
    USE SIGNAL ;
    SHAPE ABUTMENT ;
    PORT
      LAYER M4 ;
      RECT 0.000 17.856 0.024 17.880 ;
    END
  END rd_out_A[25]
  PIN rd_out_B[25]
    DIRECTION OUTPUT ;
    USE SIGNAL ;
    SHAPE ABUTMENT ;
    PORT
      LAYER M4 ;
      RECT 23.536 17.856 23.560 17.880 ;
    END
  END rd_out_B[25]
  PIN rd_out_A[26]
    DIRECTION OUTPUT ;
    USE SIGNAL ;
    SHAPE ABUTMENT ;
    PORT
      LAYER M4 ;
      RECT 0.000 18.048 0.024 18.072 ;
    END
  END rd_out_A[26]
  PIN rd_out_B[26]
    DIRECTION OUTPUT ;
    USE SIGNAL ;
    SHAPE ABUTMENT ;
    PORT
      LAYER M4 ;
      RECT 23.536 18.048 23.560 18.072 ;
    END
  END rd_out_B[26]
  PIN rd_out_A[27]
    DIRECTION OUTPUT ;
    USE SIGNAL ;
    SHAPE ABUTMENT ;
    PORT
      LAYER M4 ;
      RECT 0.000 18.240 0.024 18.264 ;
    END
  END rd_out_A[27]
  PIN rd_out_B[27]
    DIRECTION OUTPUT ;
    USE SIGNAL ;
    SHAPE ABUTMENT ;
    PORT
      LAYER M4 ;
      RECT 23.536 18.240 23.560 18.264 ;
    END
  END rd_out_B[27]
  PIN rd_out_A[28]
    DIRECTION OUTPUT ;
    USE SIGNAL ;
    SHAPE ABUTMENT ;
    PORT
      LAYER M4 ;
      RECT 0.000 18.432 0.024 18.456 ;
    END
  END rd_out_A[28]
  PIN rd_out_B[28]
    DIRECTION OUTPUT ;
    USE SIGNAL ;
    SHAPE ABUTMENT ;
    PORT
      LAYER M4 ;
      RECT 23.536 18.432 23.560 18.456 ;
    END
  END rd_out_B[28]
  PIN rd_out_A[29]
    DIRECTION OUTPUT ;
    USE SIGNAL ;
    SHAPE ABUTMENT ;
    PORT
      LAYER M4 ;
      RECT 0.000 18.624 0.024 18.648 ;
    END
  END rd_out_A[29]
  PIN rd_out_B[29]
    DIRECTION OUTPUT ;
    USE SIGNAL ;
    SHAPE ABUTMENT ;
    PORT
      LAYER M4 ;
      RECT 23.536 18.624 23.560 18.648 ;
    END
  END rd_out_B[29]
  PIN rd_out_A[30]
    DIRECTION OUTPUT ;
    USE SIGNAL ;
    SHAPE ABUTMENT ;
    PORT
      LAYER M4 ;
      RECT 0.000 18.816 0.024 18.840 ;
    END
  END rd_out_A[30]
  PIN rd_out_B[30]
    DIRECTION OUTPUT ;
    USE SIGNAL ;
    SHAPE ABUTMENT ;
    PORT
      LAYER M4 ;
      RECT 23.536 18.816 23.560 18.840 ;
    END
  END rd_out_B[30]
  PIN rd_out_A[31]
    DIRECTION OUTPUT ;
    USE SIGNAL ;
    SHAPE ABUTMENT ;
    PORT
      LAYER M4 ;
      RECT 0.000 19.008 0.024 19.032 ;
    END
  END rd_out_A[31]
  PIN rd_out_B[31]
    DIRECTION OUTPUT ;
    USE SIGNAL ;
    SHAPE ABUTMENT ;
    PORT
      LAYER M4 ;
      RECT 23.536 19.008 23.560 19.032 ;
    END
  END rd_out_B[31]
  PIN rd_out_A[32]
    DIRECTION OUTPUT ;
    USE SIGNAL ;
    SHAPE ABUTMENT ;
    PORT
      LAYER M4 ;
      RECT 0.000 19.200 0.024 19.224 ;
    END
  END rd_out_A[32]
  PIN rd_out_B[32]
    DIRECTION OUTPUT ;
    USE SIGNAL ;
    SHAPE ABUTMENT ;
    PORT
      LAYER M4 ;
      RECT 23.536 19.200 23.560 19.224 ;
    END
  END rd_out_B[32]
  PIN rd_out_A[33]
    DIRECTION OUTPUT ;
    USE SIGNAL ;
    SHAPE ABUTMENT ;
    PORT
      LAYER M4 ;
      RECT 0.000 19.392 0.024 19.416 ;
    END
  END rd_out_A[33]
  PIN rd_out_B[33]
    DIRECTION OUTPUT ;
    USE SIGNAL ;
    SHAPE ABUTMENT ;
    PORT
      LAYER M4 ;
      RECT 23.536 19.392 23.560 19.416 ;
    END
  END rd_out_B[33]
  PIN rd_out_A[34]
    DIRECTION OUTPUT ;
    USE SIGNAL ;
    SHAPE ABUTMENT ;
    PORT
      LAYER M4 ;
      RECT 0.000 19.584 0.024 19.608 ;
    END
  END rd_out_A[34]
  PIN rd_out_B[34]
    DIRECTION OUTPUT ;
    USE SIGNAL ;
    SHAPE ABUTMENT ;
    PORT
      LAYER M4 ;
      RECT 23.536 19.584 23.560 19.608 ;
    END
  END rd_out_B[34]
  PIN rd_out_A[35]
    DIRECTION OUTPUT ;
    USE SIGNAL ;
    SHAPE ABUTMENT ;
    PORT
      LAYER M4 ;
      RECT 0.000 19.776 0.024 19.800 ;
    END
  END rd_out_A[35]
  PIN rd_out_B[35]
    DIRECTION OUTPUT ;
    USE SIGNAL ;
    SHAPE ABUTMENT ;
    PORT
      LAYER M4 ;
      RECT 23.536 19.776 23.560 19.800 ;
    END
  END rd_out_B[35]
  PIN rd_out_A[36]
    DIRECTION OUTPUT ;
    USE SIGNAL ;
    SHAPE ABUTMENT ;
    PORT
      LAYER M4 ;
      RECT 0.000 19.968 0.024 19.992 ;
    END
  END rd_out_A[36]
  PIN rd_out_B[36]
    DIRECTION OUTPUT ;
    USE SIGNAL ;
    SHAPE ABUTMENT ;
    PORT
      LAYER M4 ;
      RECT 23.536 19.968 23.560 19.992 ;
    END
  END rd_out_B[36]
  PIN rd_out_A[37]
    DIRECTION OUTPUT ;
    USE SIGNAL ;
    SHAPE ABUTMENT ;
    PORT
      LAYER M4 ;
      RECT 0.000 20.160 0.024 20.184 ;
    END
  END rd_out_A[37]
  PIN rd_out_B[37]
    DIRECTION OUTPUT ;
    USE SIGNAL ;
    SHAPE ABUTMENT ;
    PORT
      LAYER M4 ;
      RECT 23.536 20.160 23.560 20.184 ;
    END
  END rd_out_B[37]
  PIN rd_out_A[38]
    DIRECTION OUTPUT ;
    USE SIGNAL ;
    SHAPE ABUTMENT ;
    PORT
      LAYER M4 ;
      RECT 0.000 20.352 0.024 20.376 ;
    END
  END rd_out_A[38]
  PIN rd_out_B[38]
    DIRECTION OUTPUT ;
    USE SIGNAL ;
    SHAPE ABUTMENT ;
    PORT
      LAYER M4 ;
      RECT 23.536 20.352 23.560 20.376 ;
    END
  END rd_out_B[38]
  PIN rd_out_A[39]
    DIRECTION OUTPUT ;
    USE SIGNAL ;
    SHAPE ABUTMENT ;
    PORT
      LAYER M4 ;
      RECT 0.000 20.544 0.024 20.568 ;
    END
  END rd_out_A[39]
  PIN rd_out_B[39]
    DIRECTION OUTPUT ;
    USE SIGNAL ;
    SHAPE ABUTMENT ;
    PORT
      LAYER M4 ;
      RECT 23.536 20.544 23.560 20.568 ;
    END
  END rd_out_B[39]
  PIN rd_out_A[40]
    DIRECTION OUTPUT ;
    USE SIGNAL ;
    SHAPE ABUTMENT ;
    PORT
      LAYER M4 ;
      RECT 0.000 20.736 0.024 20.760 ;
    END
  END rd_out_A[40]
  PIN rd_out_B[40]
    DIRECTION OUTPUT ;
    USE SIGNAL ;
    SHAPE ABUTMENT ;
    PORT
      LAYER M4 ;
      RECT 23.536 20.736 23.560 20.760 ;
    END
  END rd_out_B[40]
  PIN rd_out_A[41]
    DIRECTION OUTPUT ;
    USE SIGNAL ;
    SHAPE ABUTMENT ;
    PORT
      LAYER M4 ;
      RECT 0.000 20.928 0.024 20.952 ;
    END
  END rd_out_A[41]
  PIN rd_out_B[41]
    DIRECTION OUTPUT ;
    USE SIGNAL ;
    SHAPE ABUTMENT ;
    PORT
      LAYER M4 ;
      RECT 23.536 20.928 23.560 20.952 ;
    END
  END rd_out_B[41]
  PIN rd_out_A[42]
    DIRECTION OUTPUT ;
    USE SIGNAL ;
    SHAPE ABUTMENT ;
    PORT
      LAYER M4 ;
      RECT 0.000 21.120 0.024 21.144 ;
    END
  END rd_out_A[42]
  PIN rd_out_B[42]
    DIRECTION OUTPUT ;
    USE SIGNAL ;
    SHAPE ABUTMENT ;
    PORT
      LAYER M4 ;
      RECT 23.536 21.120 23.560 21.144 ;
    END
  END rd_out_B[42]
  PIN rd_out_A[43]
    DIRECTION OUTPUT ;
    USE SIGNAL ;
    SHAPE ABUTMENT ;
    PORT
      LAYER M4 ;
      RECT 0.000 21.312 0.024 21.336 ;
    END
  END rd_out_A[43]
  PIN rd_out_B[43]
    DIRECTION OUTPUT ;
    USE SIGNAL ;
    SHAPE ABUTMENT ;
    PORT
      LAYER M4 ;
      RECT 23.536 21.312 23.560 21.336 ;
    END
  END rd_out_B[43]
  PIN rd_out_A[44]
    DIRECTION OUTPUT ;
    USE SIGNAL ;
    SHAPE ABUTMENT ;
    PORT
      LAYER M4 ;
      RECT 0.000 21.504 0.024 21.528 ;
    END
  END rd_out_A[44]
  PIN rd_out_B[44]
    DIRECTION OUTPUT ;
    USE SIGNAL ;
    SHAPE ABUTMENT ;
    PORT
      LAYER M4 ;
      RECT 23.536 21.504 23.560 21.528 ;
    END
  END rd_out_B[44]
  PIN rd_out_A[45]
    DIRECTION OUTPUT ;
    USE SIGNAL ;
    SHAPE ABUTMENT ;
    PORT
      LAYER M4 ;
      RECT 0.000 21.696 0.024 21.720 ;
    END
  END rd_out_A[45]
  PIN rd_out_B[45]
    DIRECTION OUTPUT ;
    USE SIGNAL ;
    SHAPE ABUTMENT ;
    PORT
      LAYER M4 ;
      RECT 23.536 21.696 23.560 21.720 ;
    END
  END rd_out_B[45]
  PIN rd_out_A[46]
    DIRECTION OUTPUT ;
    USE SIGNAL ;
    SHAPE ABUTMENT ;
    PORT
      LAYER M4 ;
      RECT 0.000 21.888 0.024 21.912 ;
    END
  END rd_out_A[46]
  PIN rd_out_B[46]
    DIRECTION OUTPUT ;
    USE SIGNAL ;
    SHAPE ABUTMENT ;
    PORT
      LAYER M4 ;
      RECT 23.536 21.888 23.560 21.912 ;
    END
  END rd_out_B[46]
  PIN rd_out_A[47]
    DIRECTION OUTPUT ;
    USE SIGNAL ;
    SHAPE ABUTMENT ;
    PORT
      LAYER M4 ;
      RECT 0.000 22.080 0.024 22.104 ;
    END
  END rd_out_A[47]
  PIN rd_out_B[47]
    DIRECTION OUTPUT ;
    USE SIGNAL ;
    SHAPE ABUTMENT ;
    PORT
      LAYER M4 ;
      RECT 23.536 22.080 23.560 22.104 ;
    END
  END rd_out_B[47]
  PIN rd_out_A[48]
    DIRECTION OUTPUT ;
    USE SIGNAL ;
    SHAPE ABUTMENT ;
    PORT
      LAYER M4 ;
      RECT 0.000 22.272 0.024 22.296 ;
    END
  END rd_out_A[48]
  PIN rd_out_B[48]
    DIRECTION OUTPUT ;
    USE SIGNAL ;
    SHAPE ABUTMENT ;
    PORT
      LAYER M4 ;
      RECT 23.536 22.272 23.560 22.296 ;
    END
  END rd_out_B[48]
  PIN rd_out_A[49]
    DIRECTION OUTPUT ;
    USE SIGNAL ;
    SHAPE ABUTMENT ;
    PORT
      LAYER M4 ;
      RECT 0.000 22.464 0.024 22.488 ;
    END
  END rd_out_A[49]
  PIN rd_out_B[49]
    DIRECTION OUTPUT ;
    USE SIGNAL ;
    SHAPE ABUTMENT ;
    PORT
      LAYER M4 ;
      RECT 23.536 22.464 23.560 22.488 ;
    END
  END rd_out_B[49]
  PIN rd_out_A[50]
    DIRECTION OUTPUT ;
    USE SIGNAL ;
    SHAPE ABUTMENT ;
    PORT
      LAYER M4 ;
      RECT 0.000 22.656 0.024 22.680 ;
    END
  END rd_out_A[50]
  PIN rd_out_B[50]
    DIRECTION OUTPUT ;
    USE SIGNAL ;
    SHAPE ABUTMENT ;
    PORT
      LAYER M4 ;
      RECT 23.536 22.656 23.560 22.680 ;
    END
  END rd_out_B[50]
  PIN rd_out_A[51]
    DIRECTION OUTPUT ;
    USE SIGNAL ;
    SHAPE ABUTMENT ;
    PORT
      LAYER M4 ;
      RECT 0.000 22.848 0.024 22.872 ;
    END
  END rd_out_A[51]
  PIN rd_out_B[51]
    DIRECTION OUTPUT ;
    USE SIGNAL ;
    SHAPE ABUTMENT ;
    PORT
      LAYER M4 ;
      RECT 23.536 22.848 23.560 22.872 ;
    END
  END rd_out_B[51]
  PIN rd_out_A[52]
    DIRECTION OUTPUT ;
    USE SIGNAL ;
    SHAPE ABUTMENT ;
    PORT
      LAYER M4 ;
      RECT 0.000 23.040 0.024 23.064 ;
    END
  END rd_out_A[52]
  PIN rd_out_B[52]
    DIRECTION OUTPUT ;
    USE SIGNAL ;
    SHAPE ABUTMENT ;
    PORT
      LAYER M4 ;
      RECT 23.536 23.040 23.560 23.064 ;
    END
  END rd_out_B[52]
  PIN rd_out_A[53]
    DIRECTION OUTPUT ;
    USE SIGNAL ;
    SHAPE ABUTMENT ;
    PORT
      LAYER M4 ;
      RECT 0.000 23.232 0.024 23.256 ;
    END
  END rd_out_A[53]
  PIN rd_out_B[53]
    DIRECTION OUTPUT ;
    USE SIGNAL ;
    SHAPE ABUTMENT ;
    PORT
      LAYER M4 ;
      RECT 23.536 23.232 23.560 23.256 ;
    END
  END rd_out_B[53]
  PIN rd_out_A[54]
    DIRECTION OUTPUT ;
    USE SIGNAL ;
    SHAPE ABUTMENT ;
    PORT
      LAYER M4 ;
      RECT 0.000 23.424 0.024 23.448 ;
    END
  END rd_out_A[54]
  PIN rd_out_B[54]
    DIRECTION OUTPUT ;
    USE SIGNAL ;
    SHAPE ABUTMENT ;
    PORT
      LAYER M4 ;
      RECT 23.536 23.424 23.560 23.448 ;
    END
  END rd_out_B[54]
  PIN rd_out_A[55]
    DIRECTION OUTPUT ;
    USE SIGNAL ;
    SHAPE ABUTMENT ;
    PORT
      LAYER M4 ;
      RECT 0.000 23.616 0.024 23.640 ;
    END
  END rd_out_A[55]
  PIN rd_out_B[55]
    DIRECTION OUTPUT ;
    USE SIGNAL ;
    SHAPE ABUTMENT ;
    PORT
      LAYER M4 ;
      RECT 23.536 23.616 23.560 23.640 ;
    END
  END rd_out_B[55]
  PIN rd_out_A[56]
    DIRECTION OUTPUT ;
    USE SIGNAL ;
    SHAPE ABUTMENT ;
    PORT
      LAYER M4 ;
      RECT 0.000 23.808 0.024 23.832 ;
    END
  END rd_out_A[56]
  PIN rd_out_B[56]
    DIRECTION OUTPUT ;
    USE SIGNAL ;
    SHAPE ABUTMENT ;
    PORT
      LAYER M4 ;
      RECT 23.536 23.808 23.560 23.832 ;
    END
  END rd_out_B[56]
  PIN rd_out_A[57]
    DIRECTION OUTPUT ;
    USE SIGNAL ;
    SHAPE ABUTMENT ;
    PORT
      LAYER M4 ;
      RECT 0.000 24.000 0.024 24.024 ;
    END
  END rd_out_A[57]
  PIN rd_out_B[57]
    DIRECTION OUTPUT ;
    USE SIGNAL ;
    SHAPE ABUTMENT ;
    PORT
      LAYER M4 ;
      RECT 23.536 24.000 23.560 24.024 ;
    END
  END rd_out_B[57]
  PIN rd_out_A[58]
    DIRECTION OUTPUT ;
    USE SIGNAL ;
    SHAPE ABUTMENT ;
    PORT
      LAYER M4 ;
      RECT 0.000 24.192 0.024 24.216 ;
    END
  END rd_out_A[58]
  PIN rd_out_B[58]
    DIRECTION OUTPUT ;
    USE SIGNAL ;
    SHAPE ABUTMENT ;
    PORT
      LAYER M4 ;
      RECT 23.536 24.192 23.560 24.216 ;
    END
  END rd_out_B[58]
  PIN rd_out_A[59]
    DIRECTION OUTPUT ;
    USE SIGNAL ;
    SHAPE ABUTMENT ;
    PORT
      LAYER M4 ;
      RECT 0.000 24.384 0.024 24.408 ;
    END
  END rd_out_A[59]
  PIN rd_out_B[59]
    DIRECTION OUTPUT ;
    USE SIGNAL ;
    SHAPE ABUTMENT ;
    PORT
      LAYER M4 ;
      RECT 23.536 24.384 23.560 24.408 ;
    END
  END rd_out_B[59]
  PIN rd_out_A[60]
    DIRECTION OUTPUT ;
    USE SIGNAL ;
    SHAPE ABUTMENT ;
    PORT
      LAYER M4 ;
      RECT 0.000 24.576 0.024 24.600 ;
    END
  END rd_out_A[60]
  PIN rd_out_B[60]
    DIRECTION OUTPUT ;
    USE SIGNAL ;
    SHAPE ABUTMENT ;
    PORT
      LAYER M4 ;
      RECT 23.536 24.576 23.560 24.600 ;
    END
  END rd_out_B[60]
  PIN rd_out_A[61]
    DIRECTION OUTPUT ;
    USE SIGNAL ;
    SHAPE ABUTMENT ;
    PORT
      LAYER M4 ;
      RECT 0.000 24.768 0.024 24.792 ;
    END
  END rd_out_A[61]
  PIN rd_out_B[61]
    DIRECTION OUTPUT ;
    USE SIGNAL ;
    SHAPE ABUTMENT ;
    PORT
      LAYER M4 ;
      RECT 23.536 24.768 23.560 24.792 ;
    END
  END rd_out_B[61]
  PIN rd_out_A[62]
    DIRECTION OUTPUT ;
    USE SIGNAL ;
    SHAPE ABUTMENT ;
    PORT
      LAYER M4 ;
      RECT 0.000 24.960 0.024 24.984 ;
    END
  END rd_out_A[62]
  PIN rd_out_B[62]
    DIRECTION OUTPUT ;
    USE SIGNAL ;
    SHAPE ABUTMENT ;
    PORT
      LAYER M4 ;
      RECT 23.536 24.960 23.560 24.984 ;
    END
  END rd_out_B[62]
  PIN rd_out_A[63]
    DIRECTION OUTPUT ;
    USE SIGNAL ;
    SHAPE ABUTMENT ;
    PORT
      LAYER M4 ;
      RECT 0.000 25.152 0.024 25.176 ;
    END
  END rd_out_A[63]
  PIN rd_out_B[63]
    DIRECTION OUTPUT ;
    USE SIGNAL ;
    SHAPE ABUTMENT ;
    PORT
      LAYER M4 ;
      RECT 23.536 25.152 23.560 25.176 ;
    END
  END rd_out_B[63]
  PIN wd_in_A[0]
    DIRECTION INPUT ;
    USE SIGNAL ;
    SHAPE ABUTMENT ;
    PORT
      LAYER M4 ;
      RECT 0.000 26.064 0.024 26.088 ;
    END
  END wd_in_A[0]
  PIN wd_in_B[0]
    DIRECTION INPUT ;
    USE SIGNAL ;
    SHAPE ABUTMENT ;
    PORT
      LAYER M4 ;
      RECT 23.536 26.064 23.560 26.088 ;
    END
  END wd_in_B[0]
  PIN wd_in_A[1]
    DIRECTION INPUT ;
    USE SIGNAL ;
    SHAPE ABUTMENT ;
    PORT
      LAYER M4 ;
      RECT 0.000 26.256 0.024 26.280 ;
    END
  END wd_in_A[1]
  PIN wd_in_B[1]
    DIRECTION INPUT ;
    USE SIGNAL ;
    SHAPE ABUTMENT ;
    PORT
      LAYER M4 ;
      RECT 23.536 26.256 23.560 26.280 ;
    END
  END wd_in_B[1]
  PIN wd_in_A[2]
    DIRECTION INPUT ;
    USE SIGNAL ;
    SHAPE ABUTMENT ;
    PORT
      LAYER M4 ;
      RECT 0.000 26.448 0.024 26.472 ;
    END
  END wd_in_A[2]
  PIN wd_in_B[2]
    DIRECTION INPUT ;
    USE SIGNAL ;
    SHAPE ABUTMENT ;
    PORT
      LAYER M4 ;
      RECT 23.536 26.448 23.560 26.472 ;
    END
  END wd_in_B[2]
  PIN wd_in_A[3]
    DIRECTION INPUT ;
    USE SIGNAL ;
    SHAPE ABUTMENT ;
    PORT
      LAYER M4 ;
      RECT 0.000 26.640 0.024 26.664 ;
    END
  END wd_in_A[3]
  PIN wd_in_B[3]
    DIRECTION INPUT ;
    USE SIGNAL ;
    SHAPE ABUTMENT ;
    PORT
      LAYER M4 ;
      RECT 23.536 26.640 23.560 26.664 ;
    END
  END wd_in_B[3]
  PIN wd_in_A[4]
    DIRECTION INPUT ;
    USE SIGNAL ;
    SHAPE ABUTMENT ;
    PORT
      LAYER M4 ;
      RECT 0.000 26.832 0.024 26.856 ;
    END
  END wd_in_A[4]
  PIN wd_in_B[4]
    DIRECTION INPUT ;
    USE SIGNAL ;
    SHAPE ABUTMENT ;
    PORT
      LAYER M4 ;
      RECT 23.536 26.832 23.560 26.856 ;
    END
  END wd_in_B[4]
  PIN wd_in_A[5]
    DIRECTION INPUT ;
    USE SIGNAL ;
    SHAPE ABUTMENT ;
    PORT
      LAYER M4 ;
      RECT 0.000 27.024 0.024 27.048 ;
    END
  END wd_in_A[5]
  PIN wd_in_B[5]
    DIRECTION INPUT ;
    USE SIGNAL ;
    SHAPE ABUTMENT ;
    PORT
      LAYER M4 ;
      RECT 23.536 27.024 23.560 27.048 ;
    END
  END wd_in_B[5]
  PIN wd_in_A[6]
    DIRECTION INPUT ;
    USE SIGNAL ;
    SHAPE ABUTMENT ;
    PORT
      LAYER M4 ;
      RECT 0.000 27.216 0.024 27.240 ;
    END
  END wd_in_A[6]
  PIN wd_in_B[6]
    DIRECTION INPUT ;
    USE SIGNAL ;
    SHAPE ABUTMENT ;
    PORT
      LAYER M4 ;
      RECT 23.536 27.216 23.560 27.240 ;
    END
  END wd_in_B[6]
  PIN wd_in_A[7]
    DIRECTION INPUT ;
    USE SIGNAL ;
    SHAPE ABUTMENT ;
    PORT
      LAYER M4 ;
      RECT 0.000 27.408 0.024 27.432 ;
    END
  END wd_in_A[7]
  PIN wd_in_B[7]
    DIRECTION INPUT ;
    USE SIGNAL ;
    SHAPE ABUTMENT ;
    PORT
      LAYER M4 ;
      RECT 23.536 27.408 23.560 27.432 ;
    END
  END wd_in_B[7]
  PIN wd_in_A[8]
    DIRECTION INPUT ;
    USE SIGNAL ;
    SHAPE ABUTMENT ;
    PORT
      LAYER M4 ;
      RECT 0.000 27.600 0.024 27.624 ;
    END
  END wd_in_A[8]
  PIN wd_in_B[8]
    DIRECTION INPUT ;
    USE SIGNAL ;
    SHAPE ABUTMENT ;
    PORT
      LAYER M4 ;
      RECT 23.536 27.600 23.560 27.624 ;
    END
  END wd_in_B[8]
  PIN wd_in_A[9]
    DIRECTION INPUT ;
    USE SIGNAL ;
    SHAPE ABUTMENT ;
    PORT
      LAYER M4 ;
      RECT 0.000 27.792 0.024 27.816 ;
    END
  END wd_in_A[9]
  PIN wd_in_B[9]
    DIRECTION INPUT ;
    USE SIGNAL ;
    SHAPE ABUTMENT ;
    PORT
      LAYER M4 ;
      RECT 23.536 27.792 23.560 27.816 ;
    END
  END wd_in_B[9]
  PIN wd_in_A[10]
    DIRECTION INPUT ;
    USE SIGNAL ;
    SHAPE ABUTMENT ;
    PORT
      LAYER M4 ;
      RECT 0.000 27.984 0.024 28.008 ;
    END
  END wd_in_A[10]
  PIN wd_in_B[10]
    DIRECTION INPUT ;
    USE SIGNAL ;
    SHAPE ABUTMENT ;
    PORT
      LAYER M4 ;
      RECT 23.536 27.984 23.560 28.008 ;
    END
  END wd_in_B[10]
  PIN wd_in_A[11]
    DIRECTION INPUT ;
    USE SIGNAL ;
    SHAPE ABUTMENT ;
    PORT
      LAYER M4 ;
      RECT 0.000 28.176 0.024 28.200 ;
    END
  END wd_in_A[11]
  PIN wd_in_B[11]
    DIRECTION INPUT ;
    USE SIGNAL ;
    SHAPE ABUTMENT ;
    PORT
      LAYER M4 ;
      RECT 23.536 28.176 23.560 28.200 ;
    END
  END wd_in_B[11]
  PIN wd_in_A[12]
    DIRECTION INPUT ;
    USE SIGNAL ;
    SHAPE ABUTMENT ;
    PORT
      LAYER M4 ;
      RECT 0.000 28.368 0.024 28.392 ;
    END
  END wd_in_A[12]
  PIN wd_in_B[12]
    DIRECTION INPUT ;
    USE SIGNAL ;
    SHAPE ABUTMENT ;
    PORT
      LAYER M4 ;
      RECT 23.536 28.368 23.560 28.392 ;
    END
  END wd_in_B[12]
  PIN wd_in_A[13]
    DIRECTION INPUT ;
    USE SIGNAL ;
    SHAPE ABUTMENT ;
    PORT
      LAYER M4 ;
      RECT 0.000 28.560 0.024 28.584 ;
    END
  END wd_in_A[13]
  PIN wd_in_B[13]
    DIRECTION INPUT ;
    USE SIGNAL ;
    SHAPE ABUTMENT ;
    PORT
      LAYER M4 ;
      RECT 23.536 28.560 23.560 28.584 ;
    END
  END wd_in_B[13]
  PIN wd_in_A[14]
    DIRECTION INPUT ;
    USE SIGNAL ;
    SHAPE ABUTMENT ;
    PORT
      LAYER M4 ;
      RECT 0.000 28.752 0.024 28.776 ;
    END
  END wd_in_A[14]
  PIN wd_in_B[14]
    DIRECTION INPUT ;
    USE SIGNAL ;
    SHAPE ABUTMENT ;
    PORT
      LAYER M4 ;
      RECT 23.536 28.752 23.560 28.776 ;
    END
  END wd_in_B[14]
  PIN wd_in_A[15]
    DIRECTION INPUT ;
    USE SIGNAL ;
    SHAPE ABUTMENT ;
    PORT
      LAYER M4 ;
      RECT 0.000 28.944 0.024 28.968 ;
    END
  END wd_in_A[15]
  PIN wd_in_B[15]
    DIRECTION INPUT ;
    USE SIGNAL ;
    SHAPE ABUTMENT ;
    PORT
      LAYER M4 ;
      RECT 23.536 28.944 23.560 28.968 ;
    END
  END wd_in_B[15]
  PIN wd_in_A[16]
    DIRECTION INPUT ;
    USE SIGNAL ;
    SHAPE ABUTMENT ;
    PORT
      LAYER M4 ;
      RECT 0.000 29.136 0.024 29.160 ;
    END
  END wd_in_A[16]
  PIN wd_in_B[16]
    DIRECTION INPUT ;
    USE SIGNAL ;
    SHAPE ABUTMENT ;
    PORT
      LAYER M4 ;
      RECT 23.536 29.136 23.560 29.160 ;
    END
  END wd_in_B[16]
  PIN wd_in_A[17]
    DIRECTION INPUT ;
    USE SIGNAL ;
    SHAPE ABUTMENT ;
    PORT
      LAYER M4 ;
      RECT 0.000 29.328 0.024 29.352 ;
    END
  END wd_in_A[17]
  PIN wd_in_B[17]
    DIRECTION INPUT ;
    USE SIGNAL ;
    SHAPE ABUTMENT ;
    PORT
      LAYER M4 ;
      RECT 23.536 29.328 23.560 29.352 ;
    END
  END wd_in_B[17]
  PIN wd_in_A[18]
    DIRECTION INPUT ;
    USE SIGNAL ;
    SHAPE ABUTMENT ;
    PORT
      LAYER M4 ;
      RECT 0.000 29.520 0.024 29.544 ;
    END
  END wd_in_A[18]
  PIN wd_in_B[18]
    DIRECTION INPUT ;
    USE SIGNAL ;
    SHAPE ABUTMENT ;
    PORT
      LAYER M4 ;
      RECT 23.536 29.520 23.560 29.544 ;
    END
  END wd_in_B[18]
  PIN wd_in_A[19]
    DIRECTION INPUT ;
    USE SIGNAL ;
    SHAPE ABUTMENT ;
    PORT
      LAYER M4 ;
      RECT 0.000 29.712 0.024 29.736 ;
    END
  END wd_in_A[19]
  PIN wd_in_B[19]
    DIRECTION INPUT ;
    USE SIGNAL ;
    SHAPE ABUTMENT ;
    PORT
      LAYER M4 ;
      RECT 23.536 29.712 23.560 29.736 ;
    END
  END wd_in_B[19]
  PIN wd_in_A[20]
    DIRECTION INPUT ;
    USE SIGNAL ;
    SHAPE ABUTMENT ;
    PORT
      LAYER M4 ;
      RECT 0.000 29.904 0.024 29.928 ;
    END
  END wd_in_A[20]
  PIN wd_in_B[20]
    DIRECTION INPUT ;
    USE SIGNAL ;
    SHAPE ABUTMENT ;
    PORT
      LAYER M4 ;
      RECT 23.536 29.904 23.560 29.928 ;
    END
  END wd_in_B[20]
  PIN wd_in_A[21]
    DIRECTION INPUT ;
    USE SIGNAL ;
    SHAPE ABUTMENT ;
    PORT
      LAYER M4 ;
      RECT 0.000 30.096 0.024 30.120 ;
    END
  END wd_in_A[21]
  PIN wd_in_B[21]
    DIRECTION INPUT ;
    USE SIGNAL ;
    SHAPE ABUTMENT ;
    PORT
      LAYER M4 ;
      RECT 23.536 30.096 23.560 30.120 ;
    END
  END wd_in_B[21]
  PIN wd_in_A[22]
    DIRECTION INPUT ;
    USE SIGNAL ;
    SHAPE ABUTMENT ;
    PORT
      LAYER M4 ;
      RECT 0.000 30.288 0.024 30.312 ;
    END
  END wd_in_A[22]
  PIN wd_in_B[22]
    DIRECTION INPUT ;
    USE SIGNAL ;
    SHAPE ABUTMENT ;
    PORT
      LAYER M4 ;
      RECT 23.536 30.288 23.560 30.312 ;
    END
  END wd_in_B[22]
  PIN wd_in_A[23]
    DIRECTION INPUT ;
    USE SIGNAL ;
    SHAPE ABUTMENT ;
    PORT
      LAYER M4 ;
      RECT 0.000 30.480 0.024 30.504 ;
    END
  END wd_in_A[23]
  PIN wd_in_B[23]
    DIRECTION INPUT ;
    USE SIGNAL ;
    SHAPE ABUTMENT ;
    PORT
      LAYER M4 ;
      RECT 23.536 30.480 23.560 30.504 ;
    END
  END wd_in_B[23]
  PIN wd_in_A[24]
    DIRECTION INPUT ;
    USE SIGNAL ;
    SHAPE ABUTMENT ;
    PORT
      LAYER M4 ;
      RECT 0.000 30.672 0.024 30.696 ;
    END
  END wd_in_A[24]
  PIN wd_in_B[24]
    DIRECTION INPUT ;
    USE SIGNAL ;
    SHAPE ABUTMENT ;
    PORT
      LAYER M4 ;
      RECT 23.536 30.672 23.560 30.696 ;
    END
  END wd_in_B[24]
  PIN wd_in_A[25]
    DIRECTION INPUT ;
    USE SIGNAL ;
    SHAPE ABUTMENT ;
    PORT
      LAYER M4 ;
      RECT 0.000 30.864 0.024 30.888 ;
    END
  END wd_in_A[25]
  PIN wd_in_B[25]
    DIRECTION INPUT ;
    USE SIGNAL ;
    SHAPE ABUTMENT ;
    PORT
      LAYER M4 ;
      RECT 23.536 30.864 23.560 30.888 ;
    END
  END wd_in_B[25]
  PIN wd_in_A[26]
    DIRECTION INPUT ;
    USE SIGNAL ;
    SHAPE ABUTMENT ;
    PORT
      LAYER M4 ;
      RECT 0.000 31.056 0.024 31.080 ;
    END
  END wd_in_A[26]
  PIN wd_in_B[26]
    DIRECTION INPUT ;
    USE SIGNAL ;
    SHAPE ABUTMENT ;
    PORT
      LAYER M4 ;
      RECT 23.536 31.056 23.560 31.080 ;
    END
  END wd_in_B[26]
  PIN wd_in_A[27]
    DIRECTION INPUT ;
    USE SIGNAL ;
    SHAPE ABUTMENT ;
    PORT
      LAYER M4 ;
      RECT 0.000 31.248 0.024 31.272 ;
    END
  END wd_in_A[27]
  PIN wd_in_B[27]
    DIRECTION INPUT ;
    USE SIGNAL ;
    SHAPE ABUTMENT ;
    PORT
      LAYER M4 ;
      RECT 23.536 31.248 23.560 31.272 ;
    END
  END wd_in_B[27]
  PIN wd_in_A[28]
    DIRECTION INPUT ;
    USE SIGNAL ;
    SHAPE ABUTMENT ;
    PORT
      LAYER M4 ;
      RECT 0.000 31.440 0.024 31.464 ;
    END
  END wd_in_A[28]
  PIN wd_in_B[28]
    DIRECTION INPUT ;
    USE SIGNAL ;
    SHAPE ABUTMENT ;
    PORT
      LAYER M4 ;
      RECT 23.536 31.440 23.560 31.464 ;
    END
  END wd_in_B[28]
  PIN wd_in_A[29]
    DIRECTION INPUT ;
    USE SIGNAL ;
    SHAPE ABUTMENT ;
    PORT
      LAYER M4 ;
      RECT 0.000 31.632 0.024 31.656 ;
    END
  END wd_in_A[29]
  PIN wd_in_B[29]
    DIRECTION INPUT ;
    USE SIGNAL ;
    SHAPE ABUTMENT ;
    PORT
      LAYER M4 ;
      RECT 23.536 31.632 23.560 31.656 ;
    END
  END wd_in_B[29]
  PIN wd_in_A[30]
    DIRECTION INPUT ;
    USE SIGNAL ;
    SHAPE ABUTMENT ;
    PORT
      LAYER M4 ;
      RECT 0.000 31.824 0.024 31.848 ;
    END
  END wd_in_A[30]
  PIN wd_in_B[30]
    DIRECTION INPUT ;
    USE SIGNAL ;
    SHAPE ABUTMENT ;
    PORT
      LAYER M4 ;
      RECT 23.536 31.824 23.560 31.848 ;
    END
  END wd_in_B[30]
  PIN wd_in_A[31]
    DIRECTION INPUT ;
    USE SIGNAL ;
    SHAPE ABUTMENT ;
    PORT
      LAYER M4 ;
      RECT 0.000 32.016 0.024 32.040 ;
    END
  END wd_in_A[31]
  PIN wd_in_B[31]
    DIRECTION INPUT ;
    USE SIGNAL ;
    SHAPE ABUTMENT ;
    PORT
      LAYER M4 ;
      RECT 23.536 32.016 23.560 32.040 ;
    END
  END wd_in_B[31]
  PIN wd_in_A[32]
    DIRECTION INPUT ;
    USE SIGNAL ;
    SHAPE ABUTMENT ;
    PORT
      LAYER M4 ;
      RECT 0.000 32.208 0.024 32.232 ;
    END
  END wd_in_A[32]
  PIN wd_in_B[32]
    DIRECTION INPUT ;
    USE SIGNAL ;
    SHAPE ABUTMENT ;
    PORT
      LAYER M4 ;
      RECT 23.536 32.208 23.560 32.232 ;
    END
  END wd_in_B[32]
  PIN wd_in_A[33]
    DIRECTION INPUT ;
    USE SIGNAL ;
    SHAPE ABUTMENT ;
    PORT
      LAYER M4 ;
      RECT 0.000 32.400 0.024 32.424 ;
    END
  END wd_in_A[33]
  PIN wd_in_B[33]
    DIRECTION INPUT ;
    USE SIGNAL ;
    SHAPE ABUTMENT ;
    PORT
      LAYER M4 ;
      RECT 23.536 32.400 23.560 32.424 ;
    END
  END wd_in_B[33]
  PIN wd_in_A[34]
    DIRECTION INPUT ;
    USE SIGNAL ;
    SHAPE ABUTMENT ;
    PORT
      LAYER M4 ;
      RECT 0.000 32.592 0.024 32.616 ;
    END
  END wd_in_A[34]
  PIN wd_in_B[34]
    DIRECTION INPUT ;
    USE SIGNAL ;
    SHAPE ABUTMENT ;
    PORT
      LAYER M4 ;
      RECT 23.536 32.592 23.560 32.616 ;
    END
  END wd_in_B[34]
  PIN wd_in_A[35]
    DIRECTION INPUT ;
    USE SIGNAL ;
    SHAPE ABUTMENT ;
    PORT
      LAYER M4 ;
      RECT 0.000 32.784 0.024 32.808 ;
    END
  END wd_in_A[35]
  PIN wd_in_B[35]
    DIRECTION INPUT ;
    USE SIGNAL ;
    SHAPE ABUTMENT ;
    PORT
      LAYER M4 ;
      RECT 23.536 32.784 23.560 32.808 ;
    END
  END wd_in_B[35]
  PIN wd_in_A[36]
    DIRECTION INPUT ;
    USE SIGNAL ;
    SHAPE ABUTMENT ;
    PORT
      LAYER M4 ;
      RECT 0.000 32.976 0.024 33.000 ;
    END
  END wd_in_A[36]
  PIN wd_in_B[36]
    DIRECTION INPUT ;
    USE SIGNAL ;
    SHAPE ABUTMENT ;
    PORT
      LAYER M4 ;
      RECT 23.536 32.976 23.560 33.000 ;
    END
  END wd_in_B[36]
  PIN wd_in_A[37]
    DIRECTION INPUT ;
    USE SIGNAL ;
    SHAPE ABUTMENT ;
    PORT
      LAYER M4 ;
      RECT 0.000 33.168 0.024 33.192 ;
    END
  END wd_in_A[37]
  PIN wd_in_B[37]
    DIRECTION INPUT ;
    USE SIGNAL ;
    SHAPE ABUTMENT ;
    PORT
      LAYER M4 ;
      RECT 23.536 33.168 23.560 33.192 ;
    END
  END wd_in_B[37]
  PIN wd_in_A[38]
    DIRECTION INPUT ;
    USE SIGNAL ;
    SHAPE ABUTMENT ;
    PORT
      LAYER M4 ;
      RECT 0.000 33.360 0.024 33.384 ;
    END
  END wd_in_A[38]
  PIN wd_in_B[38]
    DIRECTION INPUT ;
    USE SIGNAL ;
    SHAPE ABUTMENT ;
    PORT
      LAYER M4 ;
      RECT 23.536 33.360 23.560 33.384 ;
    END
  END wd_in_B[38]
  PIN wd_in_A[39]
    DIRECTION INPUT ;
    USE SIGNAL ;
    SHAPE ABUTMENT ;
    PORT
      LAYER M4 ;
      RECT 0.000 33.552 0.024 33.576 ;
    END
  END wd_in_A[39]
  PIN wd_in_B[39]
    DIRECTION INPUT ;
    USE SIGNAL ;
    SHAPE ABUTMENT ;
    PORT
      LAYER M4 ;
      RECT 23.536 33.552 23.560 33.576 ;
    END
  END wd_in_B[39]
  PIN wd_in_A[40]
    DIRECTION INPUT ;
    USE SIGNAL ;
    SHAPE ABUTMENT ;
    PORT
      LAYER M4 ;
      RECT 0.000 33.744 0.024 33.768 ;
    END
  END wd_in_A[40]
  PIN wd_in_B[40]
    DIRECTION INPUT ;
    USE SIGNAL ;
    SHAPE ABUTMENT ;
    PORT
      LAYER M4 ;
      RECT 23.536 33.744 23.560 33.768 ;
    END
  END wd_in_B[40]
  PIN wd_in_A[41]
    DIRECTION INPUT ;
    USE SIGNAL ;
    SHAPE ABUTMENT ;
    PORT
      LAYER M4 ;
      RECT 0.000 33.936 0.024 33.960 ;
    END
  END wd_in_A[41]
  PIN wd_in_B[41]
    DIRECTION INPUT ;
    USE SIGNAL ;
    SHAPE ABUTMENT ;
    PORT
      LAYER M4 ;
      RECT 23.536 33.936 23.560 33.960 ;
    END
  END wd_in_B[41]
  PIN wd_in_A[42]
    DIRECTION INPUT ;
    USE SIGNAL ;
    SHAPE ABUTMENT ;
    PORT
      LAYER M4 ;
      RECT 0.000 34.128 0.024 34.152 ;
    END
  END wd_in_A[42]
  PIN wd_in_B[42]
    DIRECTION INPUT ;
    USE SIGNAL ;
    SHAPE ABUTMENT ;
    PORT
      LAYER M4 ;
      RECT 23.536 34.128 23.560 34.152 ;
    END
  END wd_in_B[42]
  PIN wd_in_A[43]
    DIRECTION INPUT ;
    USE SIGNAL ;
    SHAPE ABUTMENT ;
    PORT
      LAYER M4 ;
      RECT 0.000 34.320 0.024 34.344 ;
    END
  END wd_in_A[43]
  PIN wd_in_B[43]
    DIRECTION INPUT ;
    USE SIGNAL ;
    SHAPE ABUTMENT ;
    PORT
      LAYER M4 ;
      RECT 23.536 34.320 23.560 34.344 ;
    END
  END wd_in_B[43]
  PIN wd_in_A[44]
    DIRECTION INPUT ;
    USE SIGNAL ;
    SHAPE ABUTMENT ;
    PORT
      LAYER M4 ;
      RECT 0.000 34.512 0.024 34.536 ;
    END
  END wd_in_A[44]
  PIN wd_in_B[44]
    DIRECTION INPUT ;
    USE SIGNAL ;
    SHAPE ABUTMENT ;
    PORT
      LAYER M4 ;
      RECT 23.536 34.512 23.560 34.536 ;
    END
  END wd_in_B[44]
  PIN wd_in_A[45]
    DIRECTION INPUT ;
    USE SIGNAL ;
    SHAPE ABUTMENT ;
    PORT
      LAYER M4 ;
      RECT 0.000 34.704 0.024 34.728 ;
    END
  END wd_in_A[45]
  PIN wd_in_B[45]
    DIRECTION INPUT ;
    USE SIGNAL ;
    SHAPE ABUTMENT ;
    PORT
      LAYER M4 ;
      RECT 23.536 34.704 23.560 34.728 ;
    END
  END wd_in_B[45]
  PIN wd_in_A[46]
    DIRECTION INPUT ;
    USE SIGNAL ;
    SHAPE ABUTMENT ;
    PORT
      LAYER M4 ;
      RECT 0.000 34.896 0.024 34.920 ;
    END
  END wd_in_A[46]
  PIN wd_in_B[46]
    DIRECTION INPUT ;
    USE SIGNAL ;
    SHAPE ABUTMENT ;
    PORT
      LAYER M4 ;
      RECT 23.536 34.896 23.560 34.920 ;
    END
  END wd_in_B[46]
  PIN wd_in_A[47]
    DIRECTION INPUT ;
    USE SIGNAL ;
    SHAPE ABUTMENT ;
    PORT
      LAYER M4 ;
      RECT 0.000 35.088 0.024 35.112 ;
    END
  END wd_in_A[47]
  PIN wd_in_B[47]
    DIRECTION INPUT ;
    USE SIGNAL ;
    SHAPE ABUTMENT ;
    PORT
      LAYER M4 ;
      RECT 23.536 35.088 23.560 35.112 ;
    END
  END wd_in_B[47]
  PIN wd_in_A[48]
    DIRECTION INPUT ;
    USE SIGNAL ;
    SHAPE ABUTMENT ;
    PORT
      LAYER M4 ;
      RECT 0.000 35.280 0.024 35.304 ;
    END
  END wd_in_A[48]
  PIN wd_in_B[48]
    DIRECTION INPUT ;
    USE SIGNAL ;
    SHAPE ABUTMENT ;
    PORT
      LAYER M4 ;
      RECT 23.536 35.280 23.560 35.304 ;
    END
  END wd_in_B[48]
  PIN wd_in_A[49]
    DIRECTION INPUT ;
    USE SIGNAL ;
    SHAPE ABUTMENT ;
    PORT
      LAYER M4 ;
      RECT 0.000 35.472 0.024 35.496 ;
    END
  END wd_in_A[49]
  PIN wd_in_B[49]
    DIRECTION INPUT ;
    USE SIGNAL ;
    SHAPE ABUTMENT ;
    PORT
      LAYER M4 ;
      RECT 23.536 35.472 23.560 35.496 ;
    END
  END wd_in_B[49]
  PIN wd_in_A[50]
    DIRECTION INPUT ;
    USE SIGNAL ;
    SHAPE ABUTMENT ;
    PORT
      LAYER M4 ;
      RECT 0.000 35.664 0.024 35.688 ;
    END
  END wd_in_A[50]
  PIN wd_in_B[50]
    DIRECTION INPUT ;
    USE SIGNAL ;
    SHAPE ABUTMENT ;
    PORT
      LAYER M4 ;
      RECT 23.536 35.664 23.560 35.688 ;
    END
  END wd_in_B[50]
  PIN wd_in_A[51]
    DIRECTION INPUT ;
    USE SIGNAL ;
    SHAPE ABUTMENT ;
    PORT
      LAYER M4 ;
      RECT 0.000 35.856 0.024 35.880 ;
    END
  END wd_in_A[51]
  PIN wd_in_B[51]
    DIRECTION INPUT ;
    USE SIGNAL ;
    SHAPE ABUTMENT ;
    PORT
      LAYER M4 ;
      RECT 23.536 35.856 23.560 35.880 ;
    END
  END wd_in_B[51]
  PIN wd_in_A[52]
    DIRECTION INPUT ;
    USE SIGNAL ;
    SHAPE ABUTMENT ;
    PORT
      LAYER M4 ;
      RECT 0.000 36.048 0.024 36.072 ;
    END
  END wd_in_A[52]
  PIN wd_in_B[52]
    DIRECTION INPUT ;
    USE SIGNAL ;
    SHAPE ABUTMENT ;
    PORT
      LAYER M4 ;
      RECT 23.536 36.048 23.560 36.072 ;
    END
  END wd_in_B[52]
  PIN wd_in_A[53]
    DIRECTION INPUT ;
    USE SIGNAL ;
    SHAPE ABUTMENT ;
    PORT
      LAYER M4 ;
      RECT 0.000 36.240 0.024 36.264 ;
    END
  END wd_in_A[53]
  PIN wd_in_B[53]
    DIRECTION INPUT ;
    USE SIGNAL ;
    SHAPE ABUTMENT ;
    PORT
      LAYER M4 ;
      RECT 23.536 36.240 23.560 36.264 ;
    END
  END wd_in_B[53]
  PIN wd_in_A[54]
    DIRECTION INPUT ;
    USE SIGNAL ;
    SHAPE ABUTMENT ;
    PORT
      LAYER M4 ;
      RECT 0.000 36.432 0.024 36.456 ;
    END
  END wd_in_A[54]
  PIN wd_in_B[54]
    DIRECTION INPUT ;
    USE SIGNAL ;
    SHAPE ABUTMENT ;
    PORT
      LAYER M4 ;
      RECT 23.536 36.432 23.560 36.456 ;
    END
  END wd_in_B[54]
  PIN wd_in_A[55]
    DIRECTION INPUT ;
    USE SIGNAL ;
    SHAPE ABUTMENT ;
    PORT
      LAYER M4 ;
      RECT 0.000 36.624 0.024 36.648 ;
    END
  END wd_in_A[55]
  PIN wd_in_B[55]
    DIRECTION INPUT ;
    USE SIGNAL ;
    SHAPE ABUTMENT ;
    PORT
      LAYER M4 ;
      RECT 23.536 36.624 23.560 36.648 ;
    END
  END wd_in_B[55]
  PIN wd_in_A[56]
    DIRECTION INPUT ;
    USE SIGNAL ;
    SHAPE ABUTMENT ;
    PORT
      LAYER M4 ;
      RECT 0.000 36.816 0.024 36.840 ;
    END
  END wd_in_A[56]
  PIN wd_in_B[56]
    DIRECTION INPUT ;
    USE SIGNAL ;
    SHAPE ABUTMENT ;
    PORT
      LAYER M4 ;
      RECT 23.536 36.816 23.560 36.840 ;
    END
  END wd_in_B[56]
  PIN wd_in_A[57]
    DIRECTION INPUT ;
    USE SIGNAL ;
    SHAPE ABUTMENT ;
    PORT
      LAYER M4 ;
      RECT 0.000 37.008 0.024 37.032 ;
    END
  END wd_in_A[57]
  PIN wd_in_B[57]
    DIRECTION INPUT ;
    USE SIGNAL ;
    SHAPE ABUTMENT ;
    PORT
      LAYER M4 ;
      RECT 23.536 37.008 23.560 37.032 ;
    END
  END wd_in_B[57]
  PIN wd_in_A[58]
    DIRECTION INPUT ;
    USE SIGNAL ;
    SHAPE ABUTMENT ;
    PORT
      LAYER M4 ;
      RECT 0.000 37.200 0.024 37.224 ;
    END
  END wd_in_A[58]
  PIN wd_in_B[58]
    DIRECTION INPUT ;
    USE SIGNAL ;
    SHAPE ABUTMENT ;
    PORT
      LAYER M4 ;
      RECT 23.536 37.200 23.560 37.224 ;
    END
  END wd_in_B[58]
  PIN wd_in_A[59]
    DIRECTION INPUT ;
    USE SIGNAL ;
    SHAPE ABUTMENT ;
    PORT
      LAYER M4 ;
      RECT 0.000 37.392 0.024 37.416 ;
    END
  END wd_in_A[59]
  PIN wd_in_B[59]
    DIRECTION INPUT ;
    USE SIGNAL ;
    SHAPE ABUTMENT ;
    PORT
      LAYER M4 ;
      RECT 23.536 37.392 23.560 37.416 ;
    END
  END wd_in_B[59]
  PIN wd_in_A[60]
    DIRECTION INPUT ;
    USE SIGNAL ;
    SHAPE ABUTMENT ;
    PORT
      LAYER M4 ;
      RECT 0.000 37.584 0.024 37.608 ;
    END
  END wd_in_A[60]
  PIN wd_in_B[60]
    DIRECTION INPUT ;
    USE SIGNAL ;
    SHAPE ABUTMENT ;
    PORT
      LAYER M4 ;
      RECT 23.536 37.584 23.560 37.608 ;
    END
  END wd_in_B[60]
  PIN wd_in_A[61]
    DIRECTION INPUT ;
    USE SIGNAL ;
    SHAPE ABUTMENT ;
    PORT
      LAYER M4 ;
      RECT 0.000 37.776 0.024 37.800 ;
    END
  END wd_in_A[61]
  PIN wd_in_B[61]
    DIRECTION INPUT ;
    USE SIGNAL ;
    SHAPE ABUTMENT ;
    PORT
      LAYER M4 ;
      RECT 23.536 37.776 23.560 37.800 ;
    END
  END wd_in_B[61]
  PIN wd_in_A[62]
    DIRECTION INPUT ;
    USE SIGNAL ;
    SHAPE ABUTMENT ;
    PORT
      LAYER M4 ;
      RECT 0.000 37.968 0.024 37.992 ;
    END
  END wd_in_A[62]
  PIN wd_in_B[62]
    DIRECTION INPUT ;
    USE SIGNAL ;
    SHAPE ABUTMENT ;
    PORT
      LAYER M4 ;
      RECT 23.536 37.968 23.560 37.992 ;
    END
  END wd_in_B[62]
  PIN wd_in_A[63]
    DIRECTION INPUT ;
    USE SIGNAL ;
    SHAPE ABUTMENT ;
    PORT
      LAYER M4 ;
      RECT 0.000 38.160 0.024 38.184 ;
    END
  END wd_in_A[63]
  PIN wd_in_B[63]
    DIRECTION INPUT ;
    USE SIGNAL ;
    SHAPE ABUTMENT ;
    PORT
      LAYER M4 ;
      RECT 23.536 38.160 23.560 38.184 ;
    END
  END wd_in_B[63]
  PIN addr_in_A[0]
    DIRECTION INPUT ;
    USE SIGNAL ;
    SHAPE ABUTMENT ;
    PORT
      LAYER M4 ;
      RECT 0.000 39.072 0.024 39.096 ;
    END
  END addr_in_A[0]
  PIN addr_in_B[0]
    DIRECTION INPUT ;
    USE SIGNAL ;
    SHAPE ABUTMENT ;
    PORT
      LAYER M4 ;
      RECT 23.536 39.072 23.560 39.096 ;
    END
  END addr_in_B[0]
  PIN addr_in_A[1]
    DIRECTION INPUT ;
    USE SIGNAL ;
    SHAPE ABUTMENT ;
    PORT
      LAYER M4 ;
      RECT 0.000 39.264 0.024 39.288 ;
    END
  END addr_in_A[1]
  PIN addr_in_B[1]
    DIRECTION INPUT ;
    USE SIGNAL ;
    SHAPE ABUTMENT ;
    PORT
      LAYER M4 ;
      RECT 23.536 39.264 23.560 39.288 ;
    END
  END addr_in_B[1]
  PIN addr_in_A[2]
    DIRECTION INPUT ;
    USE SIGNAL ;
    SHAPE ABUTMENT ;
    PORT
      LAYER M4 ;
      RECT 0.000 39.456 0.024 39.480 ;
    END
  END addr_in_A[2]
  PIN addr_in_B[2]
    DIRECTION INPUT ;
    USE SIGNAL ;
    SHAPE ABUTMENT ;
    PORT
      LAYER M4 ;
      RECT 23.536 39.456 23.560 39.480 ;
    END
  END addr_in_B[2]
  PIN addr_in_A[3]
    DIRECTION INPUT ;
    USE SIGNAL ;
    SHAPE ABUTMENT ;
    PORT
      LAYER M4 ;
      RECT 0.000 39.648 0.024 39.672 ;
    END
  END addr_in_A[3]
  PIN addr_in_B[3]
    DIRECTION INPUT ;
    USE SIGNAL ;
    SHAPE ABUTMENT ;
    PORT
      LAYER M4 ;
      RECT 23.536 39.648 23.560 39.672 ;
    END
  END addr_in_B[3]
  PIN addr_in_A[4]
    DIRECTION INPUT ;
    USE SIGNAL ;
    SHAPE ABUTMENT ;
    PORT
      LAYER M4 ;
      RECT 0.000 39.840 0.024 39.864 ;
    END
  END addr_in_A[4]
  PIN addr_in_B[4]
    DIRECTION INPUT ;
    USE SIGNAL ;
    SHAPE ABUTMENT ;
    PORT
      LAYER M4 ;
      RECT 23.536 39.840 23.560 39.864 ;
    END
  END addr_in_B[4]
  PIN addr_in_A[5]
    DIRECTION INPUT ;
    USE SIGNAL ;
    SHAPE ABUTMENT ;
    PORT
      LAYER M4 ;
      RECT 0.000 40.032 0.024 40.056 ;
    END
  END addr_in_A[5]
  PIN addr_in_B[5]
    DIRECTION INPUT ;
    USE SIGNAL ;
    SHAPE ABUTMENT ;
    PORT
      LAYER M4 ;
      RECT 23.536 40.032 23.560 40.056 ;
    END
  END addr_in_B[5]
  PIN addr_in_A[6]
    DIRECTION INPUT ;
    USE SIGNAL ;
    SHAPE ABUTMENT ;
    PORT
      LAYER M4 ;
      RECT 0.000 40.224 0.024 40.248 ;
    END
  END addr_in_A[6]
  PIN addr_in_B[6]
    DIRECTION INPUT ;
    USE SIGNAL ;
    SHAPE ABUTMENT ;
    PORT
      LAYER M4 ;
      RECT 23.536 40.224 23.560 40.248 ;
    END
  END addr_in_B[6]
  PIN addr_in_A[7]
    DIRECTION INPUT ;
    USE SIGNAL ;
    SHAPE ABUTMENT ;
    PORT
      LAYER M4 ;
      RECT 0.000 40.416 0.024 40.440 ;
    END
  END addr_in_A[7]
  PIN addr_in_B[7]
    DIRECTION INPUT ;
    USE SIGNAL ;
    SHAPE ABUTMENT ;
    PORT
      LAYER M4 ;
      RECT 23.536 40.416 23.560 40.440 ;
    END
  END addr_in_B[7]
  PIN we_in_A
    DIRECTION INPUT ;
    USE SIGNAL ;
    SHAPE ABUTMENT ;
    PORT
      LAYER M4 ;
      RECT 0.000 41.328 0.024 41.352 ;
    END
  END we_in_A
  PIN we_in_B
    DIRECTION INPUT ;
    USE SIGNAL ;
    SHAPE ABUTMENT ;
    PORT
      LAYER M4 ;
      RECT 23.536 41.328 23.560 41.352 ;
    END
  END we_in_B
  PIN ce_in
    DIRECTION INPUT ;
    USE SIGNAL ;
    SHAPE ABUTMENT ;
    PORT
      LAYER M4 ;
      RECT 0.000 41.520 0.024 41.544 ;
    END
  END ce_in
  PIN clk
    DIRECTION INPUT ;
    USE SIGNAL ;
    SHAPE ABUTMENT ;
    PORT
      LAYER M4 ;
      RECT 0.000 41.712 0.024 41.736 ;
    END
  END clk
  PIN VSS
    DIRECTION INOUT ;
    USE GROUND ;
    PORT
      LAYER M4 ;
      RECT 0.048 0.000 23.512 0.096 ;
      RECT 0.048 0.768 23.512 0.864 ;
      RECT 0.048 1.536 23.512 1.632 ;
      RECT 0.048 2.304 23.512 2.400 ;
      RECT 0.048 3.072 23.512 3.168 ;
      RECT 0.048 3.840 23.512 3.936 ;
      RECT 0.048 4.608 23.512 4.704 ;
      RECT 0.048 5.376 23.512 5.472 ;
      RECT 0.048 6.144 23.512 6.240 ;
      RECT 0.048 6.912 23.512 7.008 ;
      RECT 0.048 7.680 23.512 7.776 ;
      RECT 0.048 8.448 23.512 8.544 ;
      RECT 0.048 9.216 23.512 9.312 ;
      RECT 0.048 9.984 23.512 10.080 ;
      RECT 0.048 10.752 23.512 10.848 ;
      RECT 0.048 11.520 23.512 11.616 ;
      RECT 0.048 12.288 23.512 12.384 ;
      RECT 0.048 13.056 23.512 13.152 ;
      RECT 0.048 13.824 23.512 13.920 ;
      RECT 0.048 14.592 23.512 14.688 ;
      RECT 0.048 15.360 23.512 15.456 ;
      RECT 0.048 16.128 23.512 16.224 ;
      RECT 0.048 16.896 23.512 16.992 ;
      RECT 0.048 17.664 23.512 17.760 ;
      RECT 0.048 18.432 23.512 18.528 ;
      RECT 0.048 19.200 23.512 19.296 ;
      RECT 0.048 19.968 23.512 20.064 ;
      RECT 0.048 20.736 23.512 20.832 ;
      RECT 0.048 21.504 23.512 21.600 ;
      RECT 0.048 22.272 23.512 22.368 ;
      RECT 0.048 23.040 23.512 23.136 ;
      RECT 0.048 23.808 23.512 23.904 ;
      RECT 0.048 24.576 23.512 24.672 ;
      RECT 0.048 25.344 23.512 25.440 ;
      RECT 0.048 26.112 23.512 26.208 ;
      RECT 0.048 26.880 23.512 26.976 ;
      RECT 0.048 27.648 23.512 27.744 ;
      RECT 0.048 28.416 23.512 28.512 ;
      RECT 0.048 29.184 23.512 29.280 ;
      RECT 0.048 29.952 23.512 30.048 ;
      RECT 0.048 30.720 23.512 30.816 ;
      RECT 0.048 31.488 23.512 31.584 ;
      RECT 0.048 32.256 23.512 32.352 ;
      RECT 0.048 33.024 23.512 33.120 ;
      RECT 0.048 33.792 23.512 33.888 ;
      RECT 0.048 34.560 23.512 34.656 ;
      RECT 0.048 35.328 23.512 35.424 ;
      RECT 0.048 36.096 23.512 36.192 ;
      RECT 0.048 36.864 23.512 36.960 ;
      RECT 0.048 37.632 23.512 37.728 ;
      RECT 0.048 38.400 23.512 38.496 ;
      RECT 0.048 39.168 23.512 39.264 ;
      RECT 0.048 39.936 23.512 40.032 ;
      RECT 0.048 40.704 23.512 40.800 ;
      RECT 0.048 41.472 23.512 41.568 ;
    END
  END VSS
  PIN VDD
    DIRECTION INOUT ;
    USE POWER ;
    PORT
      LAYER M4 ;
      RECT 0.048 0.384 23.512 0.480 ;
      RECT 0.048 1.152 23.512 1.248 ;
      RECT 0.048 1.920 23.512 2.016 ;
      RECT 0.048 2.688 23.512 2.784 ;
      RECT 0.048 3.456 23.512 3.552 ;
      RECT 0.048 4.224 23.512 4.320 ;
      RECT 0.048 4.992 23.512 5.088 ;
      RECT 0.048 5.760 23.512 5.856 ;
      RECT 0.048 6.528 23.512 6.624 ;
      RECT 0.048 7.296 23.512 7.392 ;
      RECT 0.048 8.064 23.512 8.160 ;
      RECT 0.048 8.832 23.512 8.928 ;
      RECT 0.048 9.600 23.512 9.696 ;
      RECT 0.048 10.368 23.512 10.464 ;
      RECT 0.048 11.136 23.512 11.232 ;
      RECT 0.048 11.904 23.512 12.000 ;
      RECT 0.048 12.672 23.512 12.768 ;
      RECT 0.048 13.440 23.512 13.536 ;
      RECT 0.048 14.208 23.512 14.304 ;
      RECT 0.048 14.976 23.512 15.072 ;
      RECT 0.048 15.744 23.512 15.840 ;
      RECT 0.048 16.512 23.512 16.608 ;
      RECT 0.048 17.280 23.512 17.376 ;
      RECT 0.048 18.048 23.512 18.144 ;
      RECT 0.048 18.816 23.512 18.912 ;
      RECT 0.048 19.584 23.512 19.680 ;
      RECT 0.048 20.352 23.512 20.448 ;
      RECT 0.048 21.120 23.512 21.216 ;
      RECT 0.048 21.888 23.512 21.984 ;
      RECT 0.048 22.656 23.512 22.752 ;
      RECT 0.048 23.424 23.512 23.520 ;
      RECT 0.048 24.192 23.512 24.288 ;
      RECT 0.048 24.960 23.512 25.056 ;
      RECT 0.048 25.728 23.512 25.824 ;
      RECT 0.048 26.496 23.512 26.592 ;
      RECT 0.048 27.264 23.512 27.360 ;
      RECT 0.048 28.032 23.512 28.128 ;
      RECT 0.048 28.800 23.512 28.896 ;
      RECT 0.048 29.568 23.512 29.664 ;
      RECT 0.048 30.336 23.512 30.432 ;
      RECT 0.048 31.104 23.512 31.200 ;
      RECT 0.048 31.872 23.512 31.968 ;
      RECT 0.048 32.640 23.512 32.736 ;
      RECT 0.048 33.408 23.512 33.504 ;
      RECT 0.048 34.176 23.512 34.272 ;
      RECT 0.048 34.944 23.512 35.040 ;
      RECT 0.048 35.712 23.512 35.808 ;
      RECT 0.048 36.480 23.512 36.576 ;
      RECT 0.048 37.248 23.512 37.344 ;
      RECT 0.048 38.016 23.512 38.112 ;
      RECT 0.048 38.784 23.512 38.880 ;
      RECT 0.048 39.552 23.512 39.648 ;
      RECT 0.048 40.320 23.512 40.416 ;
      RECT 0.048 41.088 23.512 41.184 ;
      RECT 0.048 41.856 23.512 41.952 ;
    END
  END VDD
  OBS
    LAYER M1 ;
    RECT 0 0 23.560 42.000 ;
    LAYER M2 ;
    RECT 0 0 23.560 42.000 ;
    LAYER M3 ;
    RECT 0 0 23.560 42.000 ;
    LAYER M4 ;
    RECT 0 0 23.560 42.000 ;
  END
END fakeram7_dp_256x64

END LIBRARY
